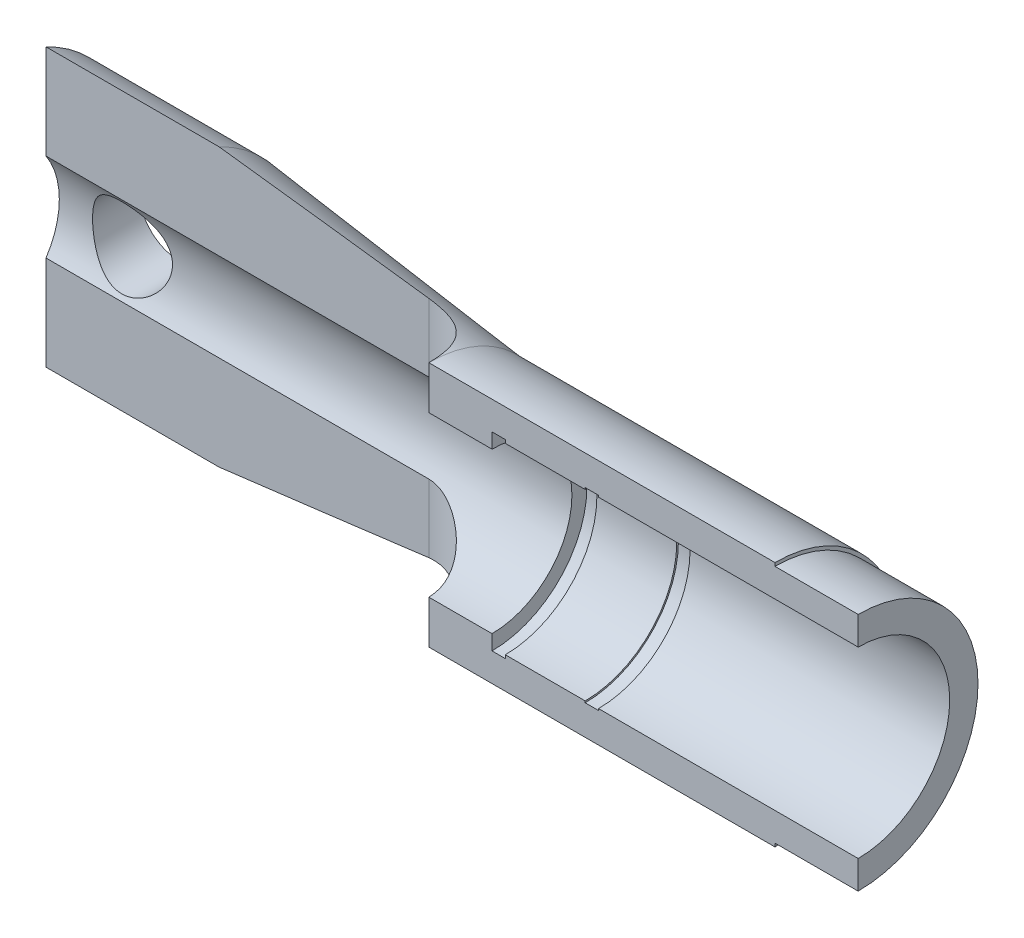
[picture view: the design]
ISO-10303-21;
HEADER;
FILE_DESCRIPTION(('STEP AP214'),'2;1');
FILE_NAME('part.step','',(''),(''),'','','');
FILE_SCHEMA(('AUTOMOTIVE_DESIGN { 1 0 10303 214 1 1 1 1 }'));
ENDSEC;
DATA;
#1=APPLICATION_CONTEXT('core data for automotive mechanical design processes');
#2=APPLICATION_PROTOCOL_DEFINITION('international standard','automotive_design',2000,#1);
#3=PRODUCT_CONTEXT('',#1,'mechanical');
#4=PRODUCT('Part','Part','',(#3));
#5=PRODUCT_RELATED_PRODUCT_CATEGORY('part','',(#4));
#6=PRODUCT_DEFINITION_FORMATION('','',#4);
#7=PRODUCT_DEFINITION_CONTEXT('part definition',#1,'design');
#8=PRODUCT_DEFINITION('design','',#6,#7);
#9=PRODUCT_DEFINITION_SHAPE('','',#8);
#10=(LENGTH_UNIT() NAMED_UNIT(*) SI_UNIT(.MILLI.,.METRE.));
#11=(NAMED_UNIT(*) PLANE_ANGLE_UNIT() SI_UNIT($,.RADIAN.));
#12=(NAMED_UNIT(*) SI_UNIT($,.STERADIAN.) SOLID_ANGLE_UNIT());
#13=UNCERTAINTY_MEASURE_WITH_UNIT(LENGTH_MEASURE(1.E-05),#10,'distance_accuracy_value','');
#14=(GEOMETRIC_REPRESENTATION_CONTEXT(3) GLOBAL_UNCERTAINTY_ASSIGNED_CONTEXT((#13)) GLOBAL_UNIT_ASSIGNED_CONTEXT((#10,
#11,#12)) REPRESENTATION_CONTEXT('',''));
#15=CARTESIAN_POINT('',(0.,0.,0.));
#16=DIRECTION('',(0.,0.,1.));
#17=DIRECTION('',(1.,0.,0.));
#18=AXIS2_PLACEMENT_3D('',#15,#16,#17);
#19=CARTESIAN_POINT('',(0.,0.,0.));
#20=DIRECTION('',(1.,0.,0.));
#21=DIRECTION('',(0.,0.,-1.));
#22=AXIS2_PLACEMENT_3D('',#19,#20,#21);
#23=CYLINDRICAL_SURFACE('',#22,27.5);
#24=CARTESIAN_POINT('',(-78.,0.,0.));
#25=DIRECTION('',(1.,0.,0.));
#26=DIRECTION('',(0.,0.,-1.));
#27=AXIS2_PLACEMENT_3D('',#24,#25,#26);
#28=CIRCLE('',#27,27.5);
#29=CARTESIAN_POINT('',(-78.,-27.5,1.92031473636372E-13));
#30=VERTEX_POINT('',#29);
#31=CARTESIAN_POINT('',(-78.,27.5,0.));
#32=VERTEX_POINT('',#31);
#33=EDGE_CURVE('E223',#30,#32,#28,.T.);
#34=ORIENTED_EDGE('',*,*,#33,.F.);
#35=DIRECTION('',(1.,0.,0.));
#36=VECTOR('',#35,1.);
#37=CARTESIAN_POINT('',(0.,-27.5,1.92031473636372E-13));
#38=LINE('',#37,#36);
#39=CARTESIAN_POINT('',(0.,-27.5,1.92031473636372E-13));
#40=VERTEX_POINT('',#39);
#41=EDGE_CURVE('E417',#30,#40,#38,.T.);
#42=ORIENTED_EDGE('',*,*,#41,.T.);
#43=CARTESIAN_POINT('',(0.,0.,0.));
#44=DIRECTION('',(1.,0.,0.));
#45=DIRECTION('',(0.,0.,-1.));
#46=AXIS2_PLACEMENT_3D('',#43,#44,#45);
#47=CIRCLE('',#46,27.5);
#48=CARTESIAN_POINT('',(0.,27.5,0.));
#49=VERTEX_POINT('',#48);
#50=EDGE_CURVE('E355',#40,#49,#47,.T.);
#51=ORIENTED_EDGE('',*,*,#50,.T.);
#52=DIRECTION('',(1.,0.,0.));
#53=VECTOR('',#52,1.);
#54=CARTESIAN_POINT('',(0.,27.5,0.));
#55=LINE('',#54,#53);
#56=EDGE_CURVE('E380',#32,#49,#55,.T.);
#57=ORIENTED_EDGE('',*,*,#56,.F.);
#58=EDGE_LOOP('',(#34,#42,#51,#57));
#59=FACE_BOUND('',#58,.T.);
#60=ADVANCED_FACE('F33',(#59),#23,.F.);
#61=CARTESIAN_POINT('',(-78.,-27.5,1.92031473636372E-13));
#62=DIRECTION('',(-1.,0.,0.));
#63=DIRECTION('',(0.,0.,1.));
#64=AXIS2_PLACEMENT_3D('',#61,#62,#63);
#65=PLANE('',#64);
#66=CARTESIAN_POINT('',(-78.,0.,0.));
#67=DIRECTION('',(1.,0.,0.));
#68=DIRECTION('',(0.,0.,-1.));
#69=AXIS2_PLACEMENT_3D('',#66,#67,#68);
#70=CIRCLE('',#69,28.);
#71=CARTESIAN_POINT('',(-78.,-28.,1.95522954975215E-13));
#72=VERTEX_POINT('',#71);
#73=CARTESIAN_POINT('',(-78.,28.,0.));
#74=VERTEX_POINT('',#73);
#75=EDGE_CURVE('E221',#72,#74,#70,.T.);
#76=ORIENTED_EDGE('',*,*,#75,.F.);
#77=DIRECTION('',(0.,1.,0.));
#78=VECTOR('',#77,1.);
#79=CARTESIAN_POINT('',(-78.,-27.5,1.92031473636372E-13));
#80=LINE('',#79,#78);
#81=EDGE_CURVE('E352',#72,#30,#80,.T.);
#82=ORIENTED_EDGE('',*,*,#81,.T.);
#83=ORIENTED_EDGE('',*,*,#33,.T.);
#84=DIRECTION('',(0.,-1.,0.));
#85=VECTOR('',#84,1.);
#86=CARTESIAN_POINT('',(-78.,27.5,0.));
#87=LINE('',#86,#85);
#88=EDGE_CURVE('E414',#74,#32,#87,.T.);
#89=ORIENTED_EDGE('',*,*,#88,.F.);
#90=EDGE_LOOP('',(#76,#82,#83,#89));
#91=FACE_BOUND('',#90,.T.);
#92=ADVANCED_FACE('F35',(#91),#65,.T.);
#93=CARTESIAN_POINT('',(0.,0.,0.));
#94=DIRECTION('',(1.,0.,0.));
#95=DIRECTION('',(0.,0.,-1.));
#96=AXIS2_PLACEMENT_3D('',#93,#94,#95);
#97=CYLINDRICAL_SURFACE('',#96,28.);
#98=CARTESIAN_POINT('',(-82.,0.,0.));
#99=DIRECTION('',(1.,0.,0.));
#100=DIRECTION('',(0.,0.,-1.));
#101=AXIS2_PLACEMENT_3D('',#98,#99,#100);
#102=CIRCLE('',#101,28.);
#103=CARTESIAN_POINT('',(-82.,-28.,1.95522954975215E-13));
#104=VERTEX_POINT('',#103);
#105=CARTESIAN_POINT('',(-82.,28.,0.));
#106=VERTEX_POINT('',#105);
#107=EDGE_CURVE('E219',#104,#106,#102,.T.);
#108=ORIENTED_EDGE('',*,*,#107,.F.);
#109=DIRECTION('',(1.,0.,0.));
#110=VECTOR('',#109,1.);
#111=CARTESIAN_POINT('',(-78.,-28.,1.95522954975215E-13));
#112=LINE('',#111,#110);
#113=EDGE_CURVE('E349',#104,#72,#112,.T.);
#114=ORIENTED_EDGE('',*,*,#113,.T.);
#115=ORIENTED_EDGE('',*,*,#75,.T.);
#116=DIRECTION('',(1.,0.,0.));
#117=VECTOR('',#116,1.);
#118=CARTESIAN_POINT('',(-78.,28.,0.));
#119=LINE('',#118,#117);
#120=EDGE_CURVE('E411',#106,#74,#119,.T.);
#121=ORIENTED_EDGE('',*,*,#120,.F.);
#122=EDGE_LOOP('',(#108,#114,#115,#121));
#123=FACE_BOUND('',#122,.T.);
#124=ADVANCED_FACE('F450',(#123),#97,.F.);
#125=CARTESIAN_POINT('',(-82.,-28.,1.95522954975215E-13));
#126=DIRECTION('',(1.,0.,0.));
#127=DIRECTION('',(0.,0.,-1.));
#128=AXIS2_PLACEMENT_3D('',#125,#126,#127);
#129=PLANE('',#128);
#130=CARTESIAN_POINT('',(-82.,0.,0.));
#131=DIRECTION('',(1.,0.,0.));
#132=DIRECTION('',(0.,0.,-1.));
#133=AXIS2_PLACEMENT_3D('',#130,#131,#132);
#134=CIRCLE('',#133,27.5);
#135=CARTESIAN_POINT('',(-82.,-27.5,1.92031473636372E-13));
#136=VERTEX_POINT('',#135);
#137=CARTESIAN_POINT('',(-82.,27.5,0.));
#138=VERTEX_POINT('',#137);
#139=EDGE_CURVE('E217',#136,#138,#134,.T.);
#140=ORIENTED_EDGE('',*,*,#139,.F.);
#141=DIRECTION('',(0.,-1.,0.));
#142=VECTOR('',#141,1.);
#143=CARTESIAN_POINT('',(-82.,-28.,1.95522954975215E-13));
#144=LINE('',#143,#142);
#145=EDGE_CURVE('E346',#136,#104,#144,.T.);
#146=ORIENTED_EDGE('',*,*,#145,.T.);
#147=ORIENTED_EDGE('',*,*,#107,.T.);
#148=DIRECTION('',(0.,1.,0.));
#149=VECTOR('',#148,1.);
#150=CARTESIAN_POINT('',(-82.,28.,0.));
#151=LINE('',#150,#149);
#152=EDGE_CURVE('E408',#138,#106,#151,.T.);
#153=ORIENTED_EDGE('',*,*,#152,.F.);
#154=EDGE_LOOP('',(#140,#146,#147,#153));
#155=FACE_BOUND('',#154,.T.);
#156=ADVANCED_FACE('F454',(#155),#129,.T.);
#157=CARTESIAN_POINT('',(0.,0.,0.));
#158=DIRECTION('',(1.,0.,0.));
#159=DIRECTION('',(0.,0.,-1.));
#160=AXIS2_PLACEMENT_3D('',#157,#158,#159);
#161=CYLINDRICAL_SURFACE('',#160,27.5);
#162=CARTESIAN_POINT('',(-106.,0.,0.));
#163=DIRECTION('',(1.,0.,0.));
#164=DIRECTION('',(0.,0.,-1.));
#165=AXIS2_PLACEMENT_3D('',#162,#163,#164);
#166=CIRCLE('',#165,27.5);
#167=CARTESIAN_POINT('',(-106.,-27.5,1.92031473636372E-13));
#168=VERTEX_POINT('',#167);
#169=CARTESIAN_POINT('',(-106.,27.5,0.));
#170=VERTEX_POINT('',#169);
#171=EDGE_CURVE('E215',#168,#170,#166,.T.);
#172=ORIENTED_EDGE('',*,*,#171,.F.);
#173=DIRECTION('',(1.,0.,0.));
#174=VECTOR('',#173,1.);
#175=CARTESIAN_POINT('',(-82.,-27.5,1.92031473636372E-13));
#176=LINE('',#175,#174);
#177=EDGE_CURVE('E343',#168,#136,#176,.T.);
#178=ORIENTED_EDGE('',*,*,#177,.T.);
#179=ORIENTED_EDGE('',*,*,#139,.T.);
#180=DIRECTION('',(1.,0.,0.));
#181=VECTOR('',#180,1.);
#182=CARTESIAN_POINT('',(-82.,27.5,0.));
#183=LINE('',#182,#181);
#184=EDGE_CURVE('E405',#170,#138,#183,.T.);
#185=ORIENTED_EDGE('',*,*,#184,.F.);
#186=EDGE_LOOP('',(#172,#178,#179,#185));
#187=FACE_BOUND('',#186,.T.);
#188=ADVANCED_FACE('F457',(#187),#161,.F.);
#189=CARTESIAN_POINT('',(-106.,-27.5,1.92031473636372E-13));
#190=DIRECTION('',(-1.,0.,0.));
#191=DIRECTION('',(0.,0.,1.));
#192=AXIS2_PLACEMENT_3D('',#189,#190,#191);
#193=PLANE('',#192);
#194=CARTESIAN_POINT('',(-106.,0.,0.));
#195=DIRECTION('',(1.,0.,0.));
#196=DIRECTION('',(0.,0.,-1.));
#197=AXIS2_PLACEMENT_3D('',#194,#195,#196);
#198=CIRCLE('',#197,28.5);
#199=CARTESIAN_POINT('',(-106.,-28.5,1.99014436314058E-13));
#200=VERTEX_POINT('',#199);
#201=CARTESIAN_POINT('',(-106.,28.5,0.));
#202=VERTEX_POINT('',#201);
#203=EDGE_CURVE('E213',#200,#202,#198,.T.);
#204=ORIENTED_EDGE('',*,*,#203,.F.);
#205=DIRECTION('',(0.,1.,0.));
#206=VECTOR('',#205,1.);
#207=CARTESIAN_POINT('',(-106.,-27.5,1.92031473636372E-13));
#208=LINE('',#207,#206);
#209=EDGE_CURVE('E340',#200,#168,#208,.T.);
#210=ORIENTED_EDGE('',*,*,#209,.T.);
#211=ORIENTED_EDGE('',*,*,#171,.T.);
#212=DIRECTION('',(0.,-1.,0.));
#213=VECTOR('',#212,1.);
#214=CARTESIAN_POINT('',(-106.,27.5,0.));
#215=LINE('',#214,#213);
#216=EDGE_CURVE('E402',#202,#170,#215,.T.);
#217=ORIENTED_EDGE('',*,*,#216,.F.);
#218=EDGE_LOOP('',(#204,#210,#211,#217));
#219=FACE_BOUND('',#218,.T.);
#220=ADVANCED_FACE('F460',(#219),#193,.T.);
#221=CARTESIAN_POINT('',(0.,0.,0.));
#222=DIRECTION('',(1.,0.,0.));
#223=DIRECTION('',(0.,0.,-1.));
#224=AXIS2_PLACEMENT_3D('',#221,#222,#223);
#225=CYLINDRICAL_SURFACE('',#224,28.5);
#226=CARTESIAN_POINT('',(-110.,0.,0.));
#227=DIRECTION('',(1.,0.,0.));
#228=DIRECTION('',(0.,0.,-1.));
#229=AXIS2_PLACEMENT_3D('',#226,#227,#228);
#230=CIRCLE('',#229,28.5);
#231=CARTESIAN_POINT('',(-110.,-28.5,1.99014436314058E-13));
#232=VERTEX_POINT('',#231);
#233=CARTESIAN_POINT('',(-110.,28.5,0.));
#234=VERTEX_POINT('',#233);
#235=EDGE_CURVE('E211',#232,#234,#230,.T.);
#236=ORIENTED_EDGE('',*,*,#235,.F.);
#237=DIRECTION('',(1.,0.,0.));
#238=VECTOR('',#237,1.);
#239=CARTESIAN_POINT('',(-106.,-28.5,1.99014436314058E-13));
#240=LINE('',#239,#238);
#241=EDGE_CURVE('E331',#232,#200,#240,.T.);
#242=ORIENTED_EDGE('',*,*,#241,.T.);
#243=ORIENTED_EDGE('',*,*,#203,.T.);
#244=DIRECTION('',(1.,0.,0.));
#245=VECTOR('',#244,1.);
#246=CARTESIAN_POINT('',(-106.,28.5,0.));
#247=LINE('',#246,#245);
#248=EDGE_CURVE('E399',#234,#202,#247,.T.);
#249=ORIENTED_EDGE('',*,*,#248,.F.);
#250=EDGE_LOOP('',(#236,#242,#243,#249));
#251=FACE_BOUND('',#250,.T.);
#252=ADVANCED_FACE('F464',(#251),#225,.F.);
#253=CARTESIAN_POINT('',(-110.,-28.5,1.99014436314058E-13));
#254=DIRECTION('',(1.,0.,0.));
#255=DIRECTION('',(0.,0.,-1.));
#256=AXIS2_PLACEMENT_3D('',#253,#254,#255);
#257=PLANE('',#256);
#258=CARTESIAN_POINT('',(-110.,0.,0.));
#259=DIRECTION('',(1.,0.,0.));
#260=DIRECTION('',(0.,0.,-1.));
#261=AXIS2_PLACEMENT_3D('',#258,#259,#260);
#262=CIRCLE('',#261,24.);
#263=CARTESIAN_POINT('',(-110.,-24.,1.6759110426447E-13));
#264=VERTEX_POINT('',#263);
#265=CARTESIAN_POINT('',(-110.,24.,0.));
#266=VERTEX_POINT('',#265);
#267=EDGE_CURVE('E203',#264,#266,#262,.T.);
#268=ORIENTED_EDGE('',*,*,#267,.F.);
#269=DIRECTION('',(0.,-1.,0.));
#270=VECTOR('',#269,1.);
#271=CARTESIAN_POINT('',(-110.,-28.5,1.99014436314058E-13));
#272=LINE('',#271,#270);
#273=EDGE_CURVE('E328',#264,#232,#272,.T.);
#274=ORIENTED_EDGE('',*,*,#273,.T.);
#275=ORIENTED_EDGE('',*,*,#235,.T.);
#276=DIRECTION('',(0.,1.,0.));
#277=VECTOR('',#276,1.);
#278=CARTESIAN_POINT('',(-110.,28.5,0.));
#279=LINE('',#278,#277);
#280=EDGE_CURVE('E396',#266,#234,#279,.T.);
#281=ORIENTED_EDGE('',*,*,#280,.F.);
#282=EDGE_LOOP('',(#268,#274,#275,#281));
#283=FACE_BOUND('',#282,.T.);
#284=ADVANCED_FACE('F289',(#283),#257,.T.);
#285=CARTESIAN_POINT('',(0.,0.,0.));
#286=DIRECTION('',(1.,0.,0.));
#287=DIRECTION('',(0.,0.,-1.));
#288=AXIS2_PLACEMENT_3D('',#285,#286,#287);
#289=CYLINDRICAL_SURFACE('',#288,24.);
#290=CARTESIAN_POINT('',(-230.,0.,-24.));
#291=CARTESIAN_POINT('',(-230.000001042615,0.315573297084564,-23.9999990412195));
#292=CARTESIAN_POINT('',(-230.012462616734,0.631168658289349,-23.99376130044));
#293=CARTESIAN_POINT('',(-230.062166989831,1.26003507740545,-23.9689674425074));
#294=CARTESIAN_POINT('',(-230.09942056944,1.57330506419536,-23.950405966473));
#295=CARTESIAN_POINT('',(-230.198350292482,2.19555871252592,-23.9014034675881));
#296=CARTESIAN_POINT('',(-230.260067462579,2.50453426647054,-23.8709424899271));
#297=CARTESIAN_POINT('',(-230.407205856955,3.11541819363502,-23.7989236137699));
#298=CARTESIAN_POINT('',(-230.492624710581,3.41732727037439,-23.7573668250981));
#299=CARTESIAN_POINT('',(-230.685882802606,4.01096204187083,-23.6643636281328));
#300=CARTESIAN_POINT('',(-230.793633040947,4.30272294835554,-23.6129565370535));
#301=CARTESIAN_POINT('',(-231.030733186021,4.87558118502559,-23.5013590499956));
#302=CARTESIAN_POINT('',(-231.160083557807,5.15667828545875,-23.4411684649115));
#303=CARTESIAN_POINT('',(-231.439243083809,5.70661678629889,-23.3133908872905));
#304=CARTESIAN_POINT('',(-231.589044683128,5.97546266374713,-23.2458066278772));
#305=CARTESIAN_POINT('',(-231.908104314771,6.49983696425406,-23.1046723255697));
#306=CARTESIAN_POINT('',(-232.07737001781,6.75536007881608,-23.0311199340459));
#307=CARTESIAN_POINT('',(-232.445005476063,7.26685384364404,-22.8750644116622));
#308=CARTESIAN_POINT('',(-232.644514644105,7.52192271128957,-22.7922889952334));
#309=CARTESIAN_POINT('',(-233.062934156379,8.01456886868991,-22.6237591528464));
#310=CARTESIAN_POINT('',(-233.281845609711,8.25214515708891,-22.5380045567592));
#311=CARTESIAN_POINT('',(-233.738046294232,8.70886687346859,-22.3654927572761));
#312=CARTESIAN_POINT('',(-233.975346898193,8.92800071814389,-22.2787349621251));
#313=CARTESIAN_POINT('',(-234.467122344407,9.34666033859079,-22.1063612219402));
#314=CARTESIAN_POINT('',(-234.721600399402,9.54618242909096,-22.0207454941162));
#315=CARTESIAN_POINT('',(-235.267031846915,9.93925333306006,-21.846304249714));
#316=CARTESIAN_POINT('',(-235.559282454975,10.13112679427,-21.7577480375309));
#317=CARTESIAN_POINT('',(-236.160750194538,10.4893097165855,-21.5873508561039));
#318=CARTESIAN_POINT('',(-236.46996006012,10.6556300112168,-21.5055070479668));
#319=CARTESIAN_POINT('',(-237.103639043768,10.9612653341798,-21.3513457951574));
#320=CARTESIAN_POINT('',(-237.428103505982,11.1005885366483,-21.2790254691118));
#321=CARTESIAN_POINT('',(-238.090263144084,11.3507342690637,-21.1466519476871));
#322=CARTESIAN_POINT('',(-238.427956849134,11.4615599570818,-21.0865973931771));
#323=CARTESIAN_POINT('',(-239.093498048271,11.6475055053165,-20.9844274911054));
#324=CARTESIAN_POINT('',(-239.420727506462,11.7243636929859,-20.9414544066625));
#325=CARTESIAN_POINT('',(-240.082059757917,11.8505186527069,-20.8703253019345));
#326=CARTESIAN_POINT('',(-240.416162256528,11.8998166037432,-20.8421686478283));
#327=CARTESIAN_POINT('',(-241.088017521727,11.9700573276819,-20.8019079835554));
#328=CARTESIAN_POINT('',(-241.425766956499,11.9910240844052,-20.7897903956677));
#329=CARTESIAN_POINT('',(-242.102003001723,12.0043296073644,-20.7821111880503));
#330=CARTESIAN_POINT('',(-242.440489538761,11.9966711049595,-20.7865479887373));
#331=CARTESIAN_POINT('',(-243.074548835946,11.9554954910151,-20.8102516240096));
#332=CARTESIAN_POINT('',(-243.370405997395,11.9251852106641,-20.8276786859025));
#333=CARTESIAN_POINT('',(-243.958091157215,11.8428838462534,-20.8745861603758));
#334=CARTESIAN_POINT('',(-244.249919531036,11.7908947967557,-20.9040654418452));
#335=CARTESIAN_POINT('',(-244.827720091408,11.6658222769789,-20.974120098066));
#336=CARTESIAN_POINT('',(-245.113690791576,11.5927335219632,-21.0146982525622));
#337=CARTESIAN_POINT('',(-245.678040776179,11.4262234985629,-21.1056960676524));
#338=CARTESIAN_POINT('',(-245.956419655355,11.3328011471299,-21.1561162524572));
#339=CARTESIAN_POINT('',(-246.510449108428,11.1240948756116,-21.2666114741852));
#340=CARTESIAN_POINT('',(-246.785889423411,11.008357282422,-21.3268820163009));
#341=CARTESIAN_POINT('',(-247.326119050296,10.7573792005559,-21.4545709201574));
#342=CARTESIAN_POINT('',(-247.590904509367,10.6221317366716,-21.5219918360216));
#343=CARTESIAN_POINT('',(-248.108671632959,10.3330565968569,-21.6622655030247));
#344=CARTESIAN_POINT('',(-248.361651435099,10.1792260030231,-21.7351191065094));
#345=CARTESIAN_POINT('',(-248.854818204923,9.85386986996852,-21.884544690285));
#346=CARTESIAN_POINT('',(-249.095004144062,9.68234291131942,-21.9611169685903));
#347=CARTESIAN_POINT('',(-249.591370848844,9.29953768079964,-22.1261694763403));
#348=CARTESIAN_POINT('',(-249.845704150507,9.08597796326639,-22.214926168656));
#349=CARTESIAN_POINT('',(-250.335672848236,8.63866698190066,-22.392662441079));
#350=CARTESIAN_POINT('',(-250.571314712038,8.40492276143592,-22.4816419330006));
#351=CARTESIAN_POINT('',(-251.022976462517,7.91809528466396,-22.6576877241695));
#352=CARTESIAN_POINT('',(-251.238978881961,7.66499517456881,-22.7447522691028));
#353=CARTESIAN_POINT('',(-251.649744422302,7.14095403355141,-22.9146812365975));
#354=CARTESIAN_POINT('',(-251.844516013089,6.87002018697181,-22.9975473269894));
#355=CARTESIAN_POINT('',(-252.220155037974,6.29847321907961,-23.1607776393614));
#356=CARTESIAN_POINT('',(-252.399945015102,5.99706449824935,-23.2408432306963));
#357=CARTESIAN_POINT('',(-252.73324308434,5.3778359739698,-23.3918881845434));
#358=CARTESIAN_POINT('',(-252.886749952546,5.06001540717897,-23.4628671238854));
#359=CARTESIAN_POINT('',(-253.165753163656,4.41031227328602,-23.5936190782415));
#360=CARTESIAN_POINT('',(-253.291267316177,4.07843880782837,-23.6533992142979));
#361=CARTESIAN_POINT('',(-253.512860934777,3.40298717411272,-23.7599772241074));
#362=CARTESIAN_POINT('',(-253.608943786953,3.05941035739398,-23.8067765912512));
#363=CARTESIAN_POINT('',(-253.763679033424,2.39232098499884,-23.8826295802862));
#364=CARTESIAN_POINT('',(-253.824772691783,2.0695039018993,-23.9128320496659));
#365=CARTESIAN_POINT('',(-253.920338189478,1.41900713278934,-23.9602323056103));
#366=CARTESIAN_POINT('',(-253.954811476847,1.09132771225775,-23.9774307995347));
#367=CARTESIAN_POINT('',(-253.996671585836,0.433945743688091,-23.9983291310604));
#368=CARTESIAN_POINT('',(-254.004069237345,0.104244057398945,-24.0020343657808));
#369=CARTESIAN_POINT('',(-253.991706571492,-0.55451434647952,-23.9958536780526));
#370=CARTESIAN_POINT('',(-253.971947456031,-0.883571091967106,-23.9859683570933));
#371=CARTESIAN_POINT('',(-253.908125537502,-1.51283492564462,-23.9541805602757));
#372=CARTESIAN_POINT('',(-253.866068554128,-1.81329854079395,-23.9332705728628));
#373=CARTESIAN_POINT('',(-253.759555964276,-2.40924407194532,-23.8806409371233));
#374=CARTESIAN_POINT('',(-253.695101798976,-2.70472630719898,-23.8489219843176));
#375=CARTESIAN_POINT('',(-253.544463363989,-3.28882114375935,-23.7754141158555));
#376=CARTESIAN_POINT('',(-253.458277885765,-3.57743336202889,-23.7336246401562));
#377=CARTESIAN_POINT('',(-253.26500583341,-4.14606176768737,-23.6409215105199));
#378=CARTESIAN_POINT('',(-253.157918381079,-4.42607759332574,-23.5900074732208));
#379=CARTESIAN_POINT('',(-252.920452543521,-4.98379006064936,-23.4786068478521));
#380=CARTESIAN_POINT('',(-252.789499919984,-5.26119588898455,-23.4178897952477));
#381=CARTESIAN_POINT('',(-252.507494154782,-5.80397665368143,-23.2893040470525));
#382=CARTESIAN_POINT('',(-252.356433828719,-6.06934724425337,-23.2214327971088));
#383=CARTESIAN_POINT('',(-252.035288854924,-6.58678352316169,-23.0799964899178));
#384=CARTESIAN_POINT('',(-251.865200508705,-6.83884661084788,-23.0064303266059));
#385=CARTESIAN_POINT('',(-251.507079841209,-7.32853684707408,-22.8551575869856));
#386=CARTESIAN_POINT('',(-251.319048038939,-7.56616441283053,-22.7774511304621));
#387=CARTESIAN_POINT('',(-250.906697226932,-8.04867125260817,-22.6117268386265));
#388=CARTESIAN_POINT('',(-250.680628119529,-8.29196695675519,-22.5234462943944));
#389=CARTESIAN_POINT('',(-250.209292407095,-8.75885661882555,-22.346024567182));
#390=CARTESIAN_POINT('',(-249.964024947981,-8.98244969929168,-22.2568833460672));
#391=CARTESIAN_POINT('',(-249.455351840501,-9.40892924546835,-22.0799769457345));
#392=CARTESIAN_POINT('',(-249.191935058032,-9.61180280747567,-21.992212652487));
#393=CARTESIAN_POINT('',(-248.648295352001,-9.99554332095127,-21.8204793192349));
#394=CARTESIAN_POINT('',(-248.36807001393,-10.1764070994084,-21.7365108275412));
#395=CARTESIAN_POINT('',(-247.778093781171,-10.5231332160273,-21.5708686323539));
#396=CARTESIAN_POINT('',(-247.467569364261,-10.6878325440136,-21.4895069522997));
#397=CARTESIAN_POINT('',(-246.831424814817,-10.9900529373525,-21.3365281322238));
#398=CARTESIAN_POINT('',(-246.505812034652,-11.1275870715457,-21.2649063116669));
#399=CARTESIAN_POINT('',(-245.841740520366,-11.3739321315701,-21.1341695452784));
#400=CARTESIAN_POINT('',(-245.503292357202,-11.4827661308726,-21.075044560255));
#401=CARTESIAN_POINT('',(-244.815940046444,-11.6703611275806,-20.9717472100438));
#402=CARTESIAN_POINT('',(-244.467037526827,-11.7491267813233,-20.9275725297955));
#403=CARTESIAN_POINT('',(-243.795770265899,-11.8692907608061,-20.8596313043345));
#404=CARTESIAN_POINT('',(-243.474073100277,-11.9135502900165,-20.8343127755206));
#405=CARTESIAN_POINT('',(-242.827327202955,-11.9758523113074,-20.7985641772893));
#406=CARTESIAN_POINT('',(-242.502278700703,-11.9938965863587,-20.7881330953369));
#407=CARTESIAN_POINT('',(-241.851783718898,-12.0034916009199,-20.7825941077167));
#408=CARTESIAN_POINT('',(-241.526337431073,-11.9950521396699,-20.7874805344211));
#409=CARTESIAN_POINT('',(-240.877793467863,-11.9518307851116,-20.8123607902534));
#410=CARTESIAN_POINT('',(-240.554695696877,-11.9170499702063,-20.8323540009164));
#411=CARTESIAN_POINT('',(-239.944262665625,-11.8262366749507,-20.8840261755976));
#412=CARTESIAN_POINT('',(-239.656462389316,-11.7725547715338,-20.9144046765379));
#413=CARTESIAN_POINT('',(-239.086724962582,-11.6446594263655,-20.9858826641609));
#414=CARTESIAN_POINT('',(-238.804789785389,-11.5704391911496,-21.0269856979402));
#415=CARTESIAN_POINT('',(-238.248531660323,-11.4022327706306,-21.1186705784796));
#416=CARTESIAN_POINT('',(-237.974207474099,-11.3082498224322,-21.16925087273));
#417=CARTESIAN_POINT('',(-237.434361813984,-11.1012865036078,-21.278513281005));
#418=CARTESIAN_POINT('',(-237.168844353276,-10.9882976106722,-21.3371990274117));
#419=CARTESIAN_POINT('',(-236.630448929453,-10.7360194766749,-21.4653024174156));
#420=CARTESIAN_POINT('',(-236.35826698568,-10.5954764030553,-21.535175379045));
#421=CARTESIAN_POINT('',(-235.826545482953,-10.2947448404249,-21.6805469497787));
#422=CARTESIAN_POINT('',(-235.56700705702,-10.1345545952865,-21.7560460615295));
#423=CARTESIAN_POINT('',(-235.061538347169,-9.79542789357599,-21.9108269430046));
#424=CARTESIAN_POINT('',(-234.815612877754,-9.61648486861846,-21.9901100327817));
#425=CARTESIAN_POINT('',(-234.338397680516,-9.24078422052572,-22.1506126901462));
#426=CARTESIAN_POINT('',(-234.107110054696,-9.04402404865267,-22.2318325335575));
#427=CARTESIAN_POINT('',(-233.632893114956,-8.60856403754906,-22.4043282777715));
#428=CARTESIAN_POINT('',(-233.391976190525,-8.36767481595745,-22.4956242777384));
#429=CARTESIAN_POINT('',(-232.931178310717,-7.86590560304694,-22.6759471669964));
#430=CARTESIAN_POINT('',(-232.711291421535,-7.60503128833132,-22.7649746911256));
#431=CARTESIAN_POINT('',(-232.293706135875,-7.06432051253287,-22.9385275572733));
#432=CARTESIAN_POINT('',(-232.096025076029,-6.78446950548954,-23.023049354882));
#433=CARTESIAN_POINT('',(-231.724545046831,-6.20747453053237,-23.1852766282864));
#434=CARTESIAN_POINT('',(-231.550744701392,-5.91033156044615,-23.2629824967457));
#435=CARTESIAN_POINT('',(-231.227374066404,-5.29822602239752,-23.4100101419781));
#436=CARTESIAN_POINT('',(-231.077989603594,-4.98314936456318,-23.4792666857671));
#437=CARTESIAN_POINT('',(-230.806583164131,-4.33929014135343,-23.6067410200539));
#438=CARTESIAN_POINT('',(-230.684557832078,-4.01050926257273,-23.664960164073));
#439=CARTESIAN_POINT('',(-230.469575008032,-3.34247342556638,-23.7685053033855));
#440=CARTESIAN_POINT('',(-230.376548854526,-3.00324533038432,-23.8138617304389));
#441=CARTESIAN_POINT('',(-230.220468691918,-2.31656786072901,-23.8904314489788));
#442=CARTESIAN_POINT('',(-230.157396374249,-1.96912364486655,-23.9216533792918));
#443=CARTESIAN_POINT('',(-230.07326131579,-1.35130022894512,-23.9634331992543));
#444=CARTESIAN_POINT('',(-230.045811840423,-1.08198201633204,-23.9771217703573));
#445=CARTESIAN_POINT('',(-230.009180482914,-0.541781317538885,-23.9954057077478));
#446=CARTESIAN_POINT('',(-229.999999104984,-0.27089878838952,-24.0000008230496));
#447=CARTESIAN_POINT('',(-230.,0.,-24.));
#448=B_SPLINE_CURVE_WITH_KNOTS('',3,(#290,#291,#292,#293,#294,#295,#296,#297,#298,#299,#300,
#301,#302,#303,#304,#305,#306,#307,#308,#309,#310,#311,#312,#313,#314,#315,#316,#317,#318,#319,
#320,#321,#322,#323,#324,#325,#326,#327,#328,#329,#330,#331,#332,#333,#334,#335,#336,#337,#338,
#339,#340,#341,#342,#343,#344,#345,#346,#347,#348,#349,#350,#351,#352,#353,#354,#355,#356,#357,
#358,#359,#360,#361,#362,#363,#364,#365,#366,#367,#368,#369,#370,#371,#372,#373,#374,#375,#376,
#377,#378,#379,#380,#381,#382,#383,#384,#385,#386,#387,#388,#389,#390,#391,#392,#393,#394,#395,
#396,#397,#398,#399,#400,#401,#402,#403,#404,#405,#406,#407,#408,#409,#410,#411,#412,#413,#414,
#415,#416,#417,#418,#419,#420,#421,#422,#423,#424,#425,#426,#427,#428,#429,#430,#431,#432,#433,
#434,#435,#436,#437,#438,#439,#440,#441,#442,#443,#444,#445,#446,#447),.UNSPECIFIED.,.T.,.F.,(4,
2,2,2,2,2,2,2,2,2,2,2,2,2,2,2,2,2,2,2,2,2,2,2,2,2,2,2,2,2,2,2,2,2,2,2,2,2,2,2,2,2,2,2,2,2,2,2,2,
2,2,2,2,2,2,2,2,2,2,2,2,2,2,2,2,2,2,2,2,2,2,2,2,2,2,2,2,2,4),(0.,0.946452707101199,
1.89331724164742,2.84177647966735,3.79014088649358,4.7347959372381,5.67947132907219,
6.62379868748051,7.56849948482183,8.57015528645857,9.57186838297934,10.5742060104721,
11.5767316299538,12.6573337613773,13.7374764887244,14.8172916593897,15.8969871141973,
16.9121438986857,17.9272572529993,18.9415107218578,19.9556674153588,20.8483627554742,
21.7409743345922,22.6338096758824,23.5266925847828,24.440125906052,25.3538866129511,
26.2677909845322,27.1817687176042,28.2119200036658,29.2417132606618,30.2724136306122,
31.3027012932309,32.381211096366,33.4597711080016,34.5376429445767,35.6153907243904,
36.603863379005,37.5922822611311,38.5803057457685,39.5682855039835,40.4795666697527,
41.3907892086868,42.3020624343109,43.2133739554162,44.1505216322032,45.0880050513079,
46.0256710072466,46.9633098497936,47.9931243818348,49.0229847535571,50.0534826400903,
51.0841289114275,52.1650777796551,53.24550534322,54.3250616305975,55.4044506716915,
56.3802259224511,57.3559348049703,58.3312827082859,59.3065906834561,60.1886227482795,
61.0709469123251,61.953126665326,62.8357030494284,63.7773264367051,64.7190340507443,
65.6610726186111,66.603246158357,67.6601582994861,68.7167713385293,69.7742036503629,
70.831575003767,71.8966527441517,72.961599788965,74.0240058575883,75.0857617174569,
75.8982062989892,76.7106733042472),.UNSPECIFIED.);
#449=CARTESIAN_POINT('',(-230.,0.,-24.));
#450=VERTEX_POINT('',#449);
#451=EDGE_CURVE('E184',#450,#450,#448,.T.);
#452=ORIENTED_EDGE('',*,*,#451,.F.);
#453=EDGE_LOOP('',(#452));
#454=FACE_BOUND('',#453,.T.);
#455=DIRECTION('',(1.,0.,0.));
#456=VECTOR('',#455,1.);
#457=CARTESIAN_POINT('',(0.,-13.2664991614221,-19.9999999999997));
#458=LINE('',#457,#456);
#459=CARTESIAN_POINT('',(-149.,-13.2664991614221,-19.9999999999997));
#460=VERTEX_POINT('',#459);
#461=CARTESIAN_POINT('',(-264.,-13.2664991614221,-19.9999999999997));
#462=VERTEX_POINT('',#461);
#463=EDGE_CURVE('E322',#460,#462,#458,.F.);
#464=ORIENTED_EDGE('',*,*,#463,.F.);
#465=CARTESIAN_POINT('',(-129.,-24.,1.74938985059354E-13));
#466=CARTESIAN_POINT('',(-128.999993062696,-24.0000072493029,-0.238682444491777));
#467=CARTESIAN_POINT('',(-129.004272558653,-23.9964395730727,-0.477360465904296));
#468=CARTESIAN_POINT('',(-129.021352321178,-23.9822084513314,-0.954188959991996));
#469=CARTESIAN_POINT('',(-129.034152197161,-23.9715453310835,-1.19233945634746));
#470=CARTESIAN_POINT('',(-129.06820886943,-23.943187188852,-1.6674520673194));
#471=CARTESIAN_POINT('',(-129.089459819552,-23.9254970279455,-1.90441488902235));
#472=CARTESIAN_POINT('',(-129.140310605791,-23.8831963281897,-2.37680451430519));
#473=CARTESIAN_POINT('',(-129.169910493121,-23.8585857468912,-2.61223130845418));
#474=CARTESIAN_POINT('',(-129.270528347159,-23.7750001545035,-3.31189563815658));
#475=CARTESIAN_POINT('',(-129.353639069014,-23.7060418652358,-3.77329657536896));
#476=CARTESIAN_POINT('',(-129.550833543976,-23.5428762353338,-4.68482014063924));
#477=CARTESIAN_POINT('',(-129.664921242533,-23.4486656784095,-5.13494132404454));
#478=CARTESIAN_POINT('',(-129.921949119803,-23.2371836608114,-6.01994428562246));
#479=CARTESIAN_POINT('',(-130.064813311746,-23.1199729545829,-6.45486273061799));
#480=CARTESIAN_POINT('',(-130.377598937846,-22.8645070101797,-7.30840731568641));
#481=CARTESIAN_POINT('',(-130.547519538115,-22.7262524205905,-7.7270339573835));
#482=CARTESIAN_POINT('',(-130.912706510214,-22.4307523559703,-8.5470227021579));
#483=CARTESIAN_POINT('',(-131.108014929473,-22.273475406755,-8.94835465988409));
#484=CARTESIAN_POINT('',(-131.521806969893,-21.942466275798,-9.73186217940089));
#485=CARTESIAN_POINT('',(-131.740295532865,-21.7687305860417,-10.1140336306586));
#486=CARTESIAN_POINT('',(-132.28261708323,-21.3408942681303,-10.9948073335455));
#487=CARTESIAN_POINT('',(-132.615716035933,-21.0806720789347,-11.4847626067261));
#488=CARTESIAN_POINT('',(-133.31774732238,-20.5397889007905,-12.4262647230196));
#489=CARTESIAN_POINT('',(-133.686691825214,-20.2591209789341,-12.8777984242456));
#490=CARTESIAN_POINT('',(-134.458073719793,-19.6825242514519,-13.742963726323));
#491=CARTESIAN_POINT('',(-134.860586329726,-19.3865617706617,-14.156505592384));
#492=CARTESIAN_POINT('',(-135.696065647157,-18.7859067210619,-14.9443990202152));
#493=CARTESIAN_POINT('',(-136.129028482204,-18.481215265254,-15.3187555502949));
#494=CARTESIAN_POINT('',(-137.032437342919,-17.8636982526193,-16.0348300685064));
#495=CARTESIAN_POINT('',(-137.503424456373,-17.5508258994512,-16.3758251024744));
#496=CARTESIAN_POINT('',(-138.475690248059,-16.9298844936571,-17.0169976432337));
#497=CARTESIAN_POINT('',(-138.976979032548,-16.6218170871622,-17.3171614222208));
#498=CARTESIAN_POINT('',(-140.009630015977,-16.0203188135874,-17.8750389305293));
#499=CARTESIAN_POINT('',(-140.540930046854,-15.7268598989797,-18.1328363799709));
#500=CARTESIAN_POINT('',(-141.361871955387,-15.3064087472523,-18.4864142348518));
#501=CARTESIAN_POINT('',(-141.639425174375,-15.1695885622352,-18.5987231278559));
#502=CARTESIAN_POINT('',(-142.202800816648,-14.9043630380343,-18.8119362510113));
#503=CARTESIAN_POINT('',(-142.488624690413,-14.7759591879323,-18.9128384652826));
#504=CARTESIAN_POINT('',(-143.436219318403,-14.3736355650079,-19.2229622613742));
#505=CARTESIAN_POINT('',(-144.116129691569,-14.1211393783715,-19.4077201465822));
#506=CARTESIAN_POINT('',(-145.164413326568,-13.8058453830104,-19.6320005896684));
#507=CARTESIAN_POINT('',(-145.517907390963,-13.711437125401,-19.6978790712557));
#508=CARTESIAN_POINT('',(-146.233465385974,-13.5474209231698,-19.8110396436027));
#509=CARTESIAN_POINT('',(-146.595524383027,-13.477799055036,-19.8583321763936));
#510=CARTESIAN_POINT('',(-147.296354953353,-13.3713308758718,-19.9301616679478));
#511=CARTESIAN_POINT('',(-147.634628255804,-13.3322810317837,-19.95623540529));
#512=CARTESIAN_POINT('',(-148.144720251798,-13.2929510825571,-19.9824340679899));
#513=CARTESIAN_POINT('',(-148.315521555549,-13.2830481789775,-19.989015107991));
#514=CARTESIAN_POINT('',(-148.657540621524,-13.269816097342,-19.9978002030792));
#515=CARTESIAN_POINT('',(-148.828758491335,-13.2664888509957,-20.0000029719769));
#516=CARTESIAN_POINT('',(-149.,-13.2664991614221,-19.9999999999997));
#517=B_SPLINE_CURVE_WITH_KNOTS('',3,(#465,#466,#467,#468,#469,#470,#471,#472,#473,#474,#475,
#476,#477,#478,#479,#480,#481,#482,#483,#484,#485,#486,#487,#488,#489,#490,#491,#492,#493,#494,
#495,#496,#497,#498,#499,#500,#501,#502,#503,#504,#505,#506,#507,#508,#509,#510,#511,#512,#513,
#514,#515,#516),.UNSPECIFIED.,.F.,.F.,(4,2,2,2,2,2,2,2,2,2,2,2,2,2,2,2,2,2,2,2,2,2,2,2,2,4),(0.,
0.71597444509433,1.43191607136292,2.14736329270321,2.86281490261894,4.28237144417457,
5.7021088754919,7.11814539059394,8.53413827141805,9.95250694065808,11.371178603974,
13.3096611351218,15.2488040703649,17.1924153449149,19.1357798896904,21.1147206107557,
23.0943250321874,25.0699692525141,26.0571592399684,27.0445234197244,29.2810473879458,
30.395254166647,31.5088340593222,32.5319287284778,33.0454103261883,33.5590427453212),.UNSPECIFIED.);
#518=CARTESIAN_POINT('',(-129.,-24.,0.));
#519=VERTEX_POINT('',#518);
#520=EDGE_CURVE('E279',#519,#460,#517,.T.);
#521=ORIENTED_EDGE('',*,*,#520,.F.);
#522=DIRECTION('',(1.,0.,0.));
#523=VECTOR('',#522,1.);
#524=CARTESIAN_POINT('',(-110.,-24.,1.6759110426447E-13));
#525=LINE('',#524,#523);
#526=EDGE_CURVE('E319',#519,#264,#525,.T.);
#527=ORIENTED_EDGE('',*,*,#526,.T.);
#528=ORIENTED_EDGE('',*,*,#267,.T.);
#529=DIRECTION('',(1.,0.,0.));
#530=VECTOR('',#529,1.);
#531=CARTESIAN_POINT('',(-110.,24.,0.));
#532=LINE('',#531,#530);
#533=CARTESIAN_POINT('',(-129.,24.,0.));
#534=VERTEX_POINT('',#533);
#535=EDGE_CURVE('E394',#534,#266,#532,.T.);
#536=ORIENTED_EDGE('',*,*,#535,.F.);
#537=CARTESIAN_POINT('',(-149.,13.2664991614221,-19.9999999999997));
#538=CARTESIAN_POINT('',(-148.821346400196,13.2664874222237,-20.0000032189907));
#539=CARTESIAN_POINT('',(-148.642721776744,13.2701097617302,-19.9976054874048));
#540=CARTESIAN_POINT('',(-148.285913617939,13.2845098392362,-19.9880441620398));
#541=CARTESIAN_POINT('',(-148.107730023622,13.2952865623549,-19.9808812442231));
#542=CARTESIAN_POINT('',(-147.575101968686,13.3381194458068,-19.9523385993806));
#543=CARTESIAN_POINT('',(-147.221810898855,13.3806792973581,-19.9239046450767));
#544=CARTESIAN_POINT('',(-146.526514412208,13.4908059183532,-19.8494945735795));
#545=CARTESIAN_POINT('',(-146.184419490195,13.5579973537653,-19.8037814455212));
#546=CARTESIAN_POINT('',(-145.507866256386,13.7144660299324,-19.6957469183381));
#547=CARTESIAN_POINT('',(-145.173412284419,13.8037554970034,-19.6334163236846));
#548=CARTESIAN_POINT('',(-144.382476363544,14.0402269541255,-19.4653676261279));
#549=CARTESIAN_POINT('',(-143.930231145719,14.1963222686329,-19.3522472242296));
#550=CARTESIAN_POINT('',(-143.044404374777,14.5362143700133,-19.0982578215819));
#551=CARTESIAN_POINT('',(-142.610830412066,14.7200222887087,-18.957377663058));
#552=CARTESIAN_POINT('',(-141.758928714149,15.109216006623,-18.6486929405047));
#553=CARTESIAN_POINT('',(-141.340748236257,15.3147605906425,-18.4806847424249));
#554=CARTESIAN_POINT('',(-140.522683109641,15.73985014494,-18.1200140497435));
#555=CARTESIAN_POINT('',(-140.122798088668,15.959394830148,-17.9273520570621));
#556=CARTESIAN_POINT('',(-139.167390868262,16.5065341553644,-17.4277223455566));
#557=CARTESIAN_POINT('',(-138.621310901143,16.8389475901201,-17.1079020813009));
#558=CARTESIAN_POINT('',(-137.564313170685,17.510244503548,-16.4201906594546));
#559=CARTESIAN_POINT('',(-137.053410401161,17.8491306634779,-16.0522791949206));
#560=CARTESIAN_POINT('',(-136.068244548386,18.5230022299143,-15.26972504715));
#561=CARTESIAN_POINT('',(-135.593904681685,18.857994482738,-14.8551850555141));
#562=CARTESIAN_POINT('',(-134.682514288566,19.5164363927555,-13.9788756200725));
#563=CARTESIAN_POINT('',(-134.245449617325,19.8398904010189,-13.5171242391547));
#564=CARTESIAN_POINT('',(-133.500018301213,20.4010495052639,-12.6492988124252));
#565=CARTESIAN_POINT('',(-133.183998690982,20.6424073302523,-12.2521433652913));
#566=CARTESIAN_POINT('',(-132.579193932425,21.1093800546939,-11.4288247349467));
#567=CARTESIAN_POINT('',(-132.290407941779,21.3349954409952,-11.0026624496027));
#568=CARTESIAN_POINT('',(-131.742938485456,21.7664378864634,-10.1223569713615));
#569=CARTESIAN_POINT('',(-131.48422842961,21.9722823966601,-9.66823904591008));
#570=CARTESIAN_POINT('',(-131.120946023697,22.2633183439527,-8.96709202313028));
#571=CARTESIAN_POINT('',(-131.00398713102,22.3573712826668,-8.73005932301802));
#572=CARTESIAN_POINT('',(-130.778672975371,22.5391286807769,-8.24946631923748));
#573=CARTESIAN_POINT('',(-130.67031997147,22.6268314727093,-8.00590432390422));
#574=CARTESIAN_POINT('',(-130.394683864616,22.8505513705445,-7.35107120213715));
#575=CARTESIAN_POINT('',(-130.235258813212,22.9806108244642,-6.93439212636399));
#576=CARTESIAN_POINT('',(-129.943187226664,23.2197132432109,-6.08597868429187));
#577=CARTESIAN_POINT('',(-129.810535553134,23.3287602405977,-5.65424722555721));
#578=CARTESIAN_POINT('',(-129.573976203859,23.523730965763,-4.77858884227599));
#579=CARTESIAN_POINT('',(-129.470023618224,23.6096908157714,-4.33468218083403));
#580=CARTESIAN_POINT('',(-129.292233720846,23.7569688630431,-3.43703261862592));
#581=CARTESIAN_POINT('',(-129.218383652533,23.818297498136,-2.98329397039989));
#582=CARTESIAN_POINT('',(-129.107044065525,23.9108516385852,-2.10885007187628));
#583=CARTESIAN_POINT('',(-129.066948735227,23.9442330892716,-1.68870802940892));
#584=CARTESIAN_POINT('',(-129.026806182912,23.9776651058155,-1.05648771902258));
#585=CARTESIAN_POINT('',(-129.016758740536,23.9860357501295,-0.845418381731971));
#586=CARTESIAN_POINT('',(-129.003354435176,23.9972045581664,-0.422907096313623));
#587=CARTESIAN_POINT('',(-128.999997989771,24.0000023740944,-0.211465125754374));
#588=CARTESIAN_POINT('',(-129.,24.,0.));
#589=B_SPLINE_CURVE_WITH_KNOTS('',3,(#537,#538,#539,#540,#541,#542,#543,#544,#545,#546,#547,
#548,#549,#550,#551,#552,#553,#554,#555,#556,#557,#558,#559,#560,#561,#562,#563,#564,#565,#566,
#567,#568,#569,#570,#571,#572,#573,#574,#575,#576,#577,#578,#579,#580,#581,#582,#583,#584,#585,
#586,#587,#588),.UNSPECIFIED.,.F.,.F.,(4,2,2,2,2,2,2,2,2,2,2,2,2,2,2,2,2,2,2,2,2,2,2,2,2,4),(0.,
0.535852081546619,1.0716281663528,2.14088197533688,3.19447739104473,4.2486570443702,
5.72111734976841,7.19417070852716,8.67884470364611,10.1634884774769,12.305174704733,
14.4477682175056,16.5857321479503,18.7228811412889,20.4074241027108,22.0919149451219,
23.7749050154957,24.6163228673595,25.4579608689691,26.8505788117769,28.2429292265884,
29.6330883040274,31.0226576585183,32.2912508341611,32.9255156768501,33.5598201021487),.UNSPECIFIED.);
#590=CARTESIAN_POINT('',(-149.,13.2664991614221,-19.9999999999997));
#591=VERTEX_POINT('',#590);
#592=EDGE_CURVE('E55',#591,#534,#589,.T.);
#593=ORIENTED_EDGE('',*,*,#592,.F.);
#594=DIRECTION('',(1.,0.,0.));
#595=VECTOR('',#594,1.);
#596=CARTESIAN_POINT('',(0.,13.2664991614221,-19.9999999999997));
#597=LINE('',#596,#595);
#598=CARTESIAN_POINT('',(-264.,13.2664991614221,-19.9999999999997));
#599=VERTEX_POINT('',#598);
#600=EDGE_CURVE('E378',#599,#591,#597,.T.);
#601=ORIENTED_EDGE('',*,*,#600,.F.);
#602=CARTESIAN_POINT('',(-264.,0.,0.));
#603=DIRECTION('',(1.,0.,0.));
#604=DIRECTION('',(0.,0.,-1.));
#605=AXIS2_PLACEMENT_3D('',#602,#603,#604);
#606=CIRCLE('',#605,24.);
#607=EDGE_CURVE('E200',#462,#599,#606,.T.);
#608=ORIENTED_EDGE('',*,*,#607,.F.);
#609=EDGE_LOOP('',(#464,#521,#527,#528,#536,#593,#601,#608));
#610=FACE_BOUND('',#609,.T.);
#611=ADVANCED_FACE('F284',(#454,#610),#289,.F.);
#612=CARTESIAN_POINT('',(-264.,-46.2222222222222,3.22768052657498E-13));
#613=DIRECTION('',(-1.,0.,0.));
#614=DIRECTION('',(0.,0.,1.));
#615=AXIS2_PLACEMENT_3D('',#612,#613,#614);
#616=PLANE('',#615);
#617=DIRECTION('',(0.,1.,0.));
#618=VECTOR('',#617,1.);
#619=CARTESIAN_POINT('',(-264.,43.6816859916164,-38.));
#620=LINE('',#619,#618);
#621=CARTESIAN_POINT('',(-264.,-26.3152774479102,-38.));
#622=VERTEX_POINT('',#621);
#623=CARTESIAN_POINT('',(-264.,26.3152774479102,-38.));
#624=VERTEX_POINT('',#623);
#625=EDGE_CURVE('E180',#622,#624,#620,.T.);
#626=ORIENTED_EDGE('',*,*,#625,.F.);
#627=CARTESIAN_POINT('',(-264.,0.,0.));
#628=DIRECTION('',(1.,0.,0.));
#629=DIRECTION('',(0.,0.,-1.));
#630=AXIS2_PLACEMENT_3D('',#627,#628,#629);
#631=CIRCLE('',#630,46.2222222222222);
#632=CARTESIAN_POINT('',(-264.,-41.6712590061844,-19.9999999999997));
#633=VERTEX_POINT('',#632);
#634=EDGE_CURVE('E192',#633,#622,#631,.T.);
#635=ORIENTED_EDGE('',*,*,#634,.F.);
#636=DIRECTION('',(0.,1.,0.));
#637=VECTOR('',#636,1.);
#638=CARTESIAN_POINT('',(-264.,-46.2222222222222,-19.9999999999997));
#639=LINE('',#638,#637);
#640=EDGE_CURVE('E303',#633,#462,#639,.T.);
#641=ORIENTED_EDGE('',*,*,#640,.T.);
#642=ORIENTED_EDGE('',*,*,#607,.T.);
#643=CARTESIAN_POINT('',(-264.,41.6712590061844,-19.9999999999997));
#644=VERTEX_POINT('',#643);
#645=EDGE_CURVE('E301',#599,#644,#639,.T.);
#646=ORIENTED_EDGE('',*,*,#645,.T.);
#647=EDGE_CURVE('E194',#624,#644,#631,.T.);
#648=ORIENTED_EDGE('',*,*,#647,.F.);
#649=EDGE_LOOP('',(#626,#635,#641,#642,#646,#648));
#650=FACE_BOUND('',#649,.T.);
#651=ADVANCED_FACE('F190',(#650),#616,.T.);
#652=CARTESIAN_POINT('',(0.,0.,0.));
#653=DIRECTION('',(1.,0.,0.));
#654=DIRECTION('',(0.,0.,-1.));
#655=AXIS2_PLACEMENT_3D('',#652,#653,#654);
#656=CYLINDRICAL_SURFACE('',#655,46.2222222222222);
#657=DIRECTION('',(1.,0.,0.));
#658=VECTOR('',#657,1.);
#659=CARTESIAN_POINT('',(0.,-26.3152774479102,-38.));
#660=LINE('',#659,#658);
#661=CARTESIAN_POINT('',(-219.,-26.3152774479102,-38.));
#662=VERTEX_POINT('',#661);
#663=EDGE_CURVE('E176',#662,#622,#660,.F.);
#664=ORIENTED_EDGE('',*,*,#663,.F.);
#665=CARTESIAN_POINT('',(-219.,0.,0.));
#666=DIRECTION('',(-1.,0.,0.));
#667=DIRECTION('',(0.,0.,1.));
#668=AXIS2_PLACEMENT_3D('',#665,#666,#667);
#669=CIRCLE('',#668,46.2222222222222);
#670=CARTESIAN_POINT('',(-219.,26.3152774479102,-38.));
#671=VERTEX_POINT('',#670);
#672=EDGE_CURVE('E11',#662,#671,#669,.F.);
#673=ORIENTED_EDGE('',*,*,#672,.T.);
#674=DIRECTION('',(1.,0.,0.));
#675=VECTOR('',#674,1.);
#676=CARTESIAN_POINT('',(0.,26.3152774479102,-38.));
#677=LINE('',#676,#675);
#678=EDGE_CURVE('E185',#624,#671,#677,.T.);
#679=ORIENTED_EDGE('',*,*,#678,.F.);
#680=ORIENTED_EDGE('',*,*,#647,.T.);
#681=DIRECTION('',(1.,0.,0.));
#682=VECTOR('',#681,1.);
#683=CARTESIAN_POINT('',(0.,41.6712590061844,-19.9999999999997));
#684=LINE('',#683,#682);
#685=CARTESIAN_POINT('',(-212.,41.6712590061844,-19.9999999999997));
#686=VERTEX_POINT('',#685);
#687=EDGE_CURVE('E323',#686,#644,#684,.F.);
#688=ORIENTED_EDGE('',*,*,#687,.F.);
#689=CARTESIAN_POINT('',(-212.,0.,0.));
#690=DIRECTION('',(1.,0.,0.));
#691=DIRECTION('',(0.,0.,-1.));
#692=AXIS2_PLACEMENT_3D('',#689,#690,#691);
#693=CIRCLE('',#692,46.2222222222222);
#694=CARTESIAN_POINT('',(-212.,-41.6712590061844,-19.9999999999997));
#695=VERTEX_POINT('',#694);
#696=EDGE_CURVE('E205',#695,#686,#693,.T.);
#697=ORIENTED_EDGE('',*,*,#696,.F.);
#698=DIRECTION('',(1.,0.,0.));
#699=VECTOR('',#698,1.);
#700=CARTESIAN_POINT('',(0.,-41.6712590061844,-19.9999999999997));
#701=LINE('',#700,#699);
#702=EDGE_CURVE('E199',#633,#695,#701,.T.);
#703=ORIENTED_EDGE('',*,*,#702,.F.);
#704=ORIENTED_EDGE('',*,*,#634,.T.);
#705=EDGE_LOOP('',(#664,#673,#679,#680,#688,#697,#703,#704));
#706=FACE_BOUND('',#705,.T.);
#707=ADVANCED_FACE('F197',(#706),#656,.T.);
#708=CARTESIAN_POINT('',(-129.,0.,0.));
#709=DIRECTION('',(-1.,0.,0.));
#710=DIRECTION('',(0.,0.,1.));
#711=AXIS2_PLACEMENT_3D('',#708,#709,#710);
#712=CONICAL_SURFACE('',#711,37.,0.110657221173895);
#713=CARTESIAN_POINT('',(-274.995920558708,49.320955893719,-19.9999999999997));
#714=CARTESIAN_POINT('',(-268.379183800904,48.5275800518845,-19.9999999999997));
#715=CARTESIAN_POINT('',(-261.762757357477,47.7316078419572,-19.9999999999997));
#716=CARTESIAN_POINT('',(-248.530652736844,46.1334638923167,-19.9999999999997));
#717=CARTESIAN_POINT('',(-241.914974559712,45.3312921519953,-19.9999999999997));
#718=CARTESIAN_POINT('',(-228.68415329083,43.7197008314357,-19.9999999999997));
#719=CARTESIAN_POINT('',(-222.069010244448,42.9102808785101,-19.9999999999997));
#720=CARTESIAN_POINT('',(-208.839770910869,41.2829084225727,-19.9999999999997));
#721=CARTESIAN_POINT('',(-202.225674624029,40.4649559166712,-19.9999999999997));
#722=CARTESIAN_POINT('',(-188.998754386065,38.8188512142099,-19.9999999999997));
#723=CARTESIAN_POINT('',(-182.385930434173,37.9906990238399,-19.9999999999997));
#724=CARTESIAN_POINT('',(-169.161850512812,36.3220228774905,-19.9999999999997));
#725=CARTESIAN_POINT('',(-162.550594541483,35.4814989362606,-19.9999999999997));
#726=CARTESIAN_POINT('',(-149.330263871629,33.7852470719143,-19.9999999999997));
#727=CARTESIAN_POINT('',(-142.721189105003,32.929519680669,-19.9999999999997));
#728=CARTESIAN_POINT('',(-132.809447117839,31.6315262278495,-19.9999999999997));
#729=CARTESIAN_POINT('',(-129.505836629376,31.1964602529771,-19.9999999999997));
#730=CARTESIAN_POINT('',(-122.899338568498,30.3208759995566,-19.9999999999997));
#731=CARTESIAN_POINT('',(-119.596450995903,29.8803577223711,-19.9999999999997));
#732=CARTESIAN_POINT('',(-112.991281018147,28.9930828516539,-19.9999999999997));
#733=CARTESIAN_POINT('',(-109.688998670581,28.5463258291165,-19.9999999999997));
#734=CARTESIAN_POINT('',(-103.085407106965,27.6456799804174,-19.9999999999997));
#735=CARTESIAN_POINT('',(-99.7840978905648,27.1917911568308,-19.9999999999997));
#736=CARTESIAN_POINT('',(-93.182666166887,26.2757542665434,-19.9999999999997));
#737=CARTESIAN_POINT('',(-89.8825436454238,25.8136063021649,-19.9999999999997));
#738=CARTESIAN_POINT('',(-83.2836618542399,24.8796321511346,-19.9999999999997));
#739=CARTESIAN_POINT('',(-79.9849025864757,24.4078059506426,-19.9999999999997));
#740=CARTESIAN_POINT('',(-73.3887628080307,23.45263832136,-19.9999999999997));
#741=CARTESIAN_POINT('',(-70.0913824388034,22.9692959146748,-19.9999999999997));
#742=CARTESIAN_POINT('',(-63.4986808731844,21.9888185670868,-19.9999999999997));
#743=CARTESIAN_POINT('',(-60.2033596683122,21.4916836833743,-19.9999999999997));
#744=CARTESIAN_POINT('',(-55.2622572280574,20.7332774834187,-19.9999999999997));
#745=CARTESIAN_POINT('',(-53.6155011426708,20.4783525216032,-19.9999999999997));
#746=CARTESIAN_POINT('',(-50.3227302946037,19.9637647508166,-19.9999999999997));
#747=CARTESIAN_POINT('',(-48.6767155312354,19.7041019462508,-19.9999999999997));
#748=CARTESIAN_POINT('',(-45.3855083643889,19.1794654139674,-19.9999999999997));
#749=CARTESIAN_POINT('',(-43.740315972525,18.9144916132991,-19.9999999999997));
#750=CARTESIAN_POINT('',(-40.4509094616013,18.3785094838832,-19.9999999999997));
#751=CARTESIAN_POINT('',(-38.8066953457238,18.1075011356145,-19.9999999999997));
#752=CARTESIAN_POINT('',(-37.1630423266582,17.8331128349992,-19.9999999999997));
#753=B_SPLINE_CURVE_WITH_KNOTS('',3,(#713,#714,#715,#716,#717,#718,#719,#720,#721,#722,#723,
#724,#725,#726,#727,#728,#729,#730,#731,#732,#733,#734,#735,#736,#737,#738,#739,#740,#741,#742,
#743,#744,#745,#746,#747,#748,#749,#750,#751,#752),.UNSPECIFIED.,.F.,.F.,(4,2,2,2,2,2,2,2,2,2,2,
2,2,2,2,2,2,2,2,4),(0.,19.9923958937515,39.9847937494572,59.978225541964,79.9716641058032,
99.965090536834,119.958493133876,139.951197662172,149.947599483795,159.943998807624,
169.94108894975,179.938175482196,189.935138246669,199.932115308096,209.929944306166,
219.927731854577,224.926839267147,229.925942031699,234.925113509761,239.924301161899),.UNSPECIFIED.);
#754=CARTESIAN_POINT('',(-149.,33.7399276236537,-19.9999999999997));
#755=VERTEX_POINT('',#754);
#756=EDGE_CURVE('E41',#755,#686,#753,.F.);
#757=ORIENTED_EDGE('',*,*,#756,.F.);
#758=CARTESIAN_POINT('',(-129.000000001,36.9999999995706,0.000200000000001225));
#759=CARTESIAN_POINT('',(-128.999996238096,37.0000047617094,-0.269025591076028));
#760=CARTESIAN_POINT('',(-129.005431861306,36.9976669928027,-0.538215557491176));
#761=CARTESIAN_POINT('',(-129.027155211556,36.9883451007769,-1.07606567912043));
#762=CARTESIAN_POINT('',(-129.043442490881,36.9813611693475,-1.34472585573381));
#763=CARTESIAN_POINT('',(-129.108517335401,36.9535086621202,-2.14894641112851));
#764=CARTESIAN_POINT('',(-129.173517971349,36.9257392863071,-2.68305990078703));
#765=CARTESIAN_POINT('',(-129.345684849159,36.8528123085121,-3.74085307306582));
#766=CARTESIAN_POINT('',(-129.45267454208,36.8077275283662,-4.26456691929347));
#767=CARTESIAN_POINT('',(-129.707733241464,36.7015426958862,-5.3002684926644));
#768=CARTESIAN_POINT('',(-129.855804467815,36.6404417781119,-5.81225558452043));
#769=CARTESIAN_POINT('',(-130.191428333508,36.5041402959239,-6.82053753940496));
#770=CARTESIAN_POINT('',(-130.378939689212,36.4289544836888,-7.31684819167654));
#771=CARTESIAN_POINT('',(-130.791979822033,36.2666389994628,-8.29144544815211));
#772=CARTESIAN_POINT('',(-131.017510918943,36.1795085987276,-8.76973095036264));
#773=CARTESIAN_POINT('',(-131.383082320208,36.0417429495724,-9.47174678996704));
#774=CARTESIAN_POINT('',(-131.509575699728,35.9946100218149,-9.70332779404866));
#775=CARTESIAN_POINT('',(-131.771395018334,35.8983515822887,-10.1609367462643));
#776=CARTESIAN_POINT('',(-131.906718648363,35.8492265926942,-10.3869661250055));
#777=CARTESIAN_POINT('',(-132.325693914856,35.6993635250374,-11.0564310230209));
#778=CARTESIAN_POINT('',(-132.622357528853,35.5961344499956,-11.4912578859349));
#779=CARTESIAN_POINT('',(-133.264423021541,35.3807651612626,-12.3570514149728));
#780=CARTESIAN_POINT('',(-133.611534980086,35.2684386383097,-12.7867004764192));
#781=CARTESIAN_POINT('',(-134.340067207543,35.0435619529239,-13.6158332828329));
#782=CARTESIAN_POINT('',(-134.721488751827,34.9310117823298,-14.0153159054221));
#783=CARTESIAN_POINT('',(-135.516652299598,34.7096321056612,-14.7818920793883));
#784=CARTESIAN_POINT('',(-135.930396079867,34.6008028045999,-15.1489838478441));
#785=CARTESIAN_POINT('',(-136.788299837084,34.3909335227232,-15.8486880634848));
#786=CARTESIAN_POINT('',(-137.232474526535,34.2898973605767,-16.1812836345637));
#787=CARTESIAN_POINT('',(-138.16457516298,34.0966104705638,-16.8203375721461));
#788=CARTESIAN_POINT('',(-138.653482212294,34.0047835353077,-17.1254969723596));
#789=CARTESIAN_POINT('',(-139.657858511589,33.838751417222,-17.6934159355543));
#790=CARTESIAN_POINT('',(-140.173312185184,33.764536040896,-17.9561999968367));
#791=CARTESIAN_POINT('',(-141.226683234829,33.6381350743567,-18.4366543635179));
#792=CARTESIAN_POINT('',(-141.764571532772,33.5859218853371,-18.6543810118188));
#793=CARTESIAN_POINT('',(-142.858859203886,33.5072285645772,-19.0426665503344));
#794=CARTESIAN_POINT('',(-143.415252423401,33.4807399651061,-19.2132409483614));
#795=CARTESIAN_POINT('',(-144.388100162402,33.4596336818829,-19.4656069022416));
#796=CARTESIAN_POINT('',(-144.80146563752,33.4583081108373,-19.5589279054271));
#797=CARTESIAN_POINT('',(-145.633001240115,33.4714436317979,-19.7190902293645));
#798=CARTESIAN_POINT('',(-146.051170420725,33.4859016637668,-19.7859366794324));
#799=CARTESIAN_POINT('',(-146.891139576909,33.5309674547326,-19.8930221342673));
#800=CARTESIAN_POINT('',(-147.312946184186,33.5616173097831,-19.9331911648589));
#801=CARTESIAN_POINT('',(-148.156912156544,33.6388725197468,-19.9867084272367));
#802=CARTESIAN_POINT('',(-148.579071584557,33.6854819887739,-20.0000497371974));
#803=CARTESIAN_POINT('',(-149.0002,33.7399534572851,-19.9999999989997));
#804=B_SPLINE_CURVE_WITH_KNOTS('',3,(#758,#759,#760,#761,#762,#763,#764,#765,#766,#767,#768,
#769,#770,#771,#772,#773,#774,#775,#776,#777,#778,#779,#780,#781,#782,#783,#784,#785,#786,#787,
#788,#789,#790,#791,#792,#793,#794,#795,#796,#797,#798,#799,#800,#801,#802,#803),.UNSPECIFIED.,
.F.,.F.,(4,2,2,2,2,2,2,2,2,2,2,2,2,2,2,2,2,2,2,2,2,2,4),(0.,0.80754085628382,1.61504839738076,
3.22912749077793,4.83649144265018,6.44394226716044,8.0497188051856,9.65559335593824,
10.4595689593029,11.2633351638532,12.8708176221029,14.5599392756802,16.2491237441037,
17.9384011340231,19.6285010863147,21.3769563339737,23.124397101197,24.8696393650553,
26.6143069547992,27.884551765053,29.1545503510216,30.4278670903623,31.7015123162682),.UNSPECIFIED.);
#805=CARTESIAN_POINT('',(-129.,37.,0.));
#806=VERTEX_POINT('',#805);
#807=EDGE_CURVE('E270',#806,#755,#804,.T.);
#808=ORIENTED_EDGE('',*,*,#807,.F.);
#809=CARTESIAN_POINT('',(-129.,0.,0.));
#810=DIRECTION('',(1.,0.,0.));
#811=DIRECTION('',(0.,0.,-1.));
#812=AXIS2_PLACEMENT_3D('',#809,#810,#811);
#813=CIRCLE('',#812,37.);
#814=CARTESIAN_POINT('',(-129.,-37.,2.58369619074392E-13));
#815=VERTEX_POINT('',#814);
#816=EDGE_CURVE('E362',#815,#806,#813,.T.);
#817=ORIENTED_EDGE('',*,*,#816,.F.);
#818=CARTESIAN_POINT('',(-149.0002,-33.7399534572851,-19.9999999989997));
#819=CARTESIAN_POINT('',(-148.751149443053,-33.707778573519,-20.00000371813));
#820=CARTESIAN_POINT('',(-148.501777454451,-33.6783184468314,-19.9953519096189));
#821=CARTESIAN_POINT('',(-148.002793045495,-33.6249229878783,-19.9766844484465));
#822=CARTESIAN_POINT('',(-147.753180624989,-33.6009876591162,-19.9626687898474));
#823=CARTESIAN_POINT('',(-147.004805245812,-33.5376303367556,-19.9065132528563));
#824=CARTESIAN_POINT('',(-146.5062854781,-33.5066286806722,-19.8502649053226));
#825=CARTESIAN_POINT('',(-145.516617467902,-33.4672786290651,-19.7006430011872));
#826=CARTESIAN_POINT('',(-145.025444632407,-33.4588158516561,-19.6074596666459));
#827=CARTESIAN_POINT('',(-144.051559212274,-33.4634310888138,-19.3845925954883));
#828=CARTESIAN_POINT('',(-143.568846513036,-33.4765088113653,-19.2549093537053));
#829=CARTESIAN_POINT('',(-142.615554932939,-33.5226860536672,-18.9601613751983));
#830=CARTESIAN_POINT('',(-142.144971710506,-33.5557783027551,-18.7951095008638));
#831=CARTESIAN_POINT('',(-141.218797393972,-33.6398657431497,-18.4309666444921));
#832=CARTESIAN_POINT('',(-140.76320774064,-33.6908626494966,-18.2318724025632));
#833=CARTESIAN_POINT('',(-139.869312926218,-33.808266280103,-17.8010384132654));
#834=CARTESIAN_POINT('',(-139.431023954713,-33.8746870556,-17.5692689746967));
#835=CARTESIAN_POINT('',(-138.574409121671,-34.0200984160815,-17.0748833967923));
#836=CARTESIAN_POINT('',(-138.156083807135,-34.0990893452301,-16.8122664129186));
#837=CARTESIAN_POINT('',(-137.321396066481,-34.2708025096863,-16.2443012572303));
#838=CARTESIAN_POINT('',(-136.906126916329,-34.3640068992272,-15.9374927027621));
#839=CARTESIAN_POINT('',(-136.101388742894,-34.5576522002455,-15.2935131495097));
#840=CARTESIAN_POINT('',(-135.711930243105,-34.65809602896,-14.9563298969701));
#841=CARTESIAN_POINT('',(-134.960517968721,-34.8629012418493,-14.2533416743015));
#842=CARTESIAN_POINT('',(-134.59857713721,-34.9672644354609,-13.8875233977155));
#843=CARTESIAN_POINT('',(-133.90416311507,-35.1766011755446,-13.1293540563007));
#844=CARTESIAN_POINT('',(-133.571680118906,-35.28157450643,-12.7370118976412));
#845=CARTESIAN_POINT('',(-132.904263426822,-35.5000208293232,-11.8848636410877));
#846=CARTESIAN_POINT('',(-132.57274118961,-35.6132283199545,-11.4223001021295));
#847=CARTESIAN_POINT('',(-132.105516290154,-35.7778617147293,-10.7078223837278));
#848=CARTESIAN_POINT('',(-131.954774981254,-35.8318801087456,-10.4662069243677));
#849=CARTESIAN_POINT('',(-131.663499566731,-35.9377662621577,-9.97632117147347));
#850=CARTESIAN_POINT('',(-131.522968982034,-35.9896332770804,-9.72804862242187));
#851=CARTESIAN_POINT('',(-131.117489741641,-36.1411976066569,-8.97446076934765));
#852=CARTESIAN_POINT('',(-130.868263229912,-36.2369975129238,-8.45977860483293));
#853=CARTESIAN_POINT('',(-130.414121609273,-36.414865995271,-7.40895596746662));
#854=CARTESIAN_POINT('',(-130.209201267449,-36.4969361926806,-6.87281803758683));
#855=CARTESIAN_POINT('',(-129.943173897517,-36.6049537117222,-6.07523063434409));
#856=CARTESIAN_POINT('',(-129.863863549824,-36.6374011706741,-5.82060936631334));
#857=CARTESIAN_POINT('',(-129.715398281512,-36.6984972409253,-5.30804188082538));
#858=CARTESIAN_POINT('',(-129.646240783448,-36.7271468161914,-5.05009652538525));
#859=CARTESIAN_POINT('',(-129.4542380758,-36.8070690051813,-4.27183978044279));
#860=CARTESIAN_POINT('',(-129.346827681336,-36.8523294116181,-3.7470029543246));
#861=CARTESIAN_POINT('',(-129.17406366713,-36.9255069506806,-2.68727894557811));
#862=CARTESIAN_POINT('',(-129.108863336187,-36.9533608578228,-2.15236231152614));
#863=CARTESIAN_POINT('',(-129.043583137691,-36.9813008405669,-1.34689159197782));
#864=CARTESIAN_POINT('',(-129.027243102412,-36.9883073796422,-1.07779967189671));
#865=CARTESIAN_POINT('',(-129.005449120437,-36.9976595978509,-0.539082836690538));
#866=CARTESIAN_POINT('',(-128.999995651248,-37.0000050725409,-0.26945789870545));
#867=CARTESIAN_POINT('',(-129.000000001,-36.9999999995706,0.000200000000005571));
#868=B_SPLINE_CURVE_WITH_KNOTS('',3,(#818,#819,#820,#821,#822,#823,#824,#825,#826,#827,#828,
#829,#830,#831,#832,#833,#834,#835,#836,#837,#838,#839,#840,#841,#842,#843,#844,#845,#846,#847,
#848,#849,#850,#851,#852,#853,#854,#855,#856,#857,#858,#859,#860,#861,#862,#863,#864,#865,#866,
#867),.UNSPECIFIED.,.F.,.F.,(4,2,2,2,2,2,2,2,2,2,2,2,2,2,2,2,2,2,2,2,2,2,2,2,4),(0.,
0.753242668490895,1.50648581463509,3.0123128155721,4.5104832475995,6.00863336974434,
7.50623958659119,9.00398929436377,10.5031088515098,12.0022694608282,13.5746336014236,
15.1476349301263,16.7213716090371,18.2945824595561,20.0330541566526,20.9024106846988,
21.7720655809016,23.5092032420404,25.2461356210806,26.0518932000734,26.8574458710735,
28.468218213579,30.0848078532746,30.8936151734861,31.7024579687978),.UNSPECIFIED.);
#869=CARTESIAN_POINT('',(-149.,-33.7399276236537,-19.9999999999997));
#870=VERTEX_POINT('',#869);
#871=EDGE_CURVE('E262',#870,#815,#868,.T.);
#872=ORIENTED_EDGE('',*,*,#871,.F.);
#873=CARTESIAN_POINT('',(-274.995920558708,-49.320955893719,-19.9999999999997));
#874=CARTESIAN_POINT('',(-268.379183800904,-48.5275800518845,-19.9999999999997));
#875=CARTESIAN_POINT('',(-261.762757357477,-47.7316078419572,-19.9999999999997));
#876=CARTESIAN_POINT('',(-248.530652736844,-46.1334638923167,-19.9999999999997));
#877=CARTESIAN_POINT('',(-241.914974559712,-45.3312921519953,-19.9999999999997));
#878=CARTESIAN_POINT('',(-228.68415329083,-43.7197008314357,-19.9999999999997));
#879=CARTESIAN_POINT('',(-222.069010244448,-42.9102808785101,-19.9999999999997));
#880=CARTESIAN_POINT('',(-208.839770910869,-41.2829084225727,-19.9999999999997));
#881=CARTESIAN_POINT('',(-202.225674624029,-40.4649559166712,-19.9999999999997));
#882=CARTESIAN_POINT('',(-188.998754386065,-38.8188512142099,-19.9999999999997));
#883=CARTESIAN_POINT('',(-182.385930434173,-37.9906990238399,-19.9999999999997));
#884=CARTESIAN_POINT('',(-169.161850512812,-36.3220228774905,-19.9999999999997));
#885=CARTESIAN_POINT('',(-162.550594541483,-35.4814989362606,-19.9999999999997));
#886=CARTESIAN_POINT('',(-149.330263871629,-33.7852470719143,-19.9999999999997));
#887=CARTESIAN_POINT('',(-142.721189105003,-32.929519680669,-19.9999999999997));
#888=CARTESIAN_POINT('',(-132.809447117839,-31.6315262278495,-19.9999999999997));
#889=CARTESIAN_POINT('',(-129.505836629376,-31.1964602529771,-19.9999999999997));
#890=CARTESIAN_POINT('',(-122.899338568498,-30.3208759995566,-19.9999999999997));
#891=CARTESIAN_POINT('',(-119.596450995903,-29.8803577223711,-19.9999999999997));
#892=CARTESIAN_POINT('',(-112.991281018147,-28.9930828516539,-19.9999999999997));
#893=CARTESIAN_POINT('',(-109.688998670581,-28.5463258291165,-19.9999999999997));
#894=CARTESIAN_POINT('',(-103.085407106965,-27.6456799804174,-19.9999999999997));
#895=CARTESIAN_POINT('',(-99.7840978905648,-27.1917911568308,-19.9999999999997));
#896=CARTESIAN_POINT('',(-93.182666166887,-26.2757542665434,-19.9999999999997));
#897=CARTESIAN_POINT('',(-89.8825436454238,-25.8136063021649,-19.9999999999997));
#898=CARTESIAN_POINT('',(-83.2836618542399,-24.8796321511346,-19.9999999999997));
#899=CARTESIAN_POINT('',(-79.9849025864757,-24.4078059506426,-19.9999999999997));
#900=CARTESIAN_POINT('',(-73.3887628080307,-23.45263832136,-19.9999999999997));
#901=CARTESIAN_POINT('',(-70.0913824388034,-22.9692959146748,-19.9999999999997));
#902=CARTESIAN_POINT('',(-63.4986808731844,-21.9888185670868,-19.9999999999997));
#903=CARTESIAN_POINT('',(-60.2033596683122,-21.4916836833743,-19.9999999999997));
#904=CARTESIAN_POINT('',(-55.2622572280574,-20.7332774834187,-19.9999999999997));
#905=CARTESIAN_POINT('',(-53.6155011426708,-20.4783525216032,-19.9999999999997));
#906=CARTESIAN_POINT('',(-50.3227302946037,-19.9637647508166,-19.9999999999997));
#907=CARTESIAN_POINT('',(-48.6767155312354,-19.7041019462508,-19.9999999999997));
#908=CARTESIAN_POINT('',(-45.3855083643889,-19.1794654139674,-19.9999999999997));
#909=CARTESIAN_POINT('',(-43.740315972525,-18.9144916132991,-19.9999999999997));
#910=CARTESIAN_POINT('',(-40.4509094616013,-18.3785094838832,-19.9999999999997));
#911=CARTESIAN_POINT('',(-38.8066953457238,-18.1075011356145,-19.9999999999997));
#912=CARTESIAN_POINT('',(-37.1630423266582,-17.8331128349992,-19.9999999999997));
#913=B_SPLINE_CURVE_WITH_KNOTS('',3,(#873,#874,#875,#876,#877,#878,#879,#880,#881,#882,#883,
#884,#885,#886,#887,#888,#889,#890,#891,#892,#893,#894,#895,#896,#897,#898,#899,#900,#901,#902,
#903,#904,#905,#906,#907,#908,#909,#910,#911,#912),.UNSPECIFIED.,.F.,.F.,(4,2,2,2,2,2,2,2,2,2,2,
2,2,2,2,2,2,2,2,4),(0.,19.9923958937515,39.9847937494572,59.978225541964,79.9716641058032,
99.965090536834,119.958493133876,139.951197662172,149.947599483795,159.943998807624,
169.94108894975,179.938175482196,189.935138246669,199.932115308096,209.929944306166,
219.927731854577,224.926839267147,229.925942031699,234.925113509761,239.924301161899),.UNSPECIFIED.);
#914=EDGE_CURVE('E227',#695,#870,#913,.T.);
#915=ORIENTED_EDGE('',*,*,#914,.F.);
#916=ORIENTED_EDGE('',*,*,#696,.T.);
#917=EDGE_LOOP('',(#757,#808,#817,#872,#915,#916));
#918=FACE_BOUND('',#917,.T.);
#919=ADVANCED_FACE('F237',(#918),#712,.T.);
#920=CARTESIAN_POINT('',(0.,0.,0.));
#921=DIRECTION('',(1.,0.,0.));
#922=DIRECTION('',(0.,0.,-1.));
#923=AXIS2_PLACEMENT_3D('',#920,#921,#922);
#924=CYLINDRICAL_SURFACE('',#923,37.);
#925=CARTESIAN_POINT('',(-25.,0.,0.));
#926=DIRECTION('',(1.,0.,0.));
#927=DIRECTION('',(0.,0.,-1.));
#928=AXIS2_PLACEMENT_3D('',#925,#926,#927);
#929=CIRCLE('',#928,37.);
#930=CARTESIAN_POINT('',(-25.,-37.,2.58369619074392E-13));
#931=VERTEX_POINT('',#930);
#932=CARTESIAN_POINT('',(-25.,37.,0.));
#933=VERTEX_POINT('',#932);
#934=EDGE_CURVE('E361',#931,#933,#929,.T.);
#935=ORIENTED_EDGE('',*,*,#934,.F.);
#936=DIRECTION('',(-1.,0.,0.));
#937=VECTOR('',#936,1.);
#938=CARTESIAN_POINT('',(-129.,-37.,2.58369619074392E-13));
#939=LINE('',#938,#937);
#940=EDGE_CURVE('E329',#931,#815,#939,.T.);
#941=ORIENTED_EDGE('',*,*,#940,.T.);
#942=ORIENTED_EDGE('',*,*,#816,.T.);
#943=DIRECTION('',(-1.,0.,0.));
#944=VECTOR('',#943,1.);
#945=CARTESIAN_POINT('',(-129.,37.,0.));
#946=LINE('',#945,#944);
#947=EDGE_CURVE('E392',#933,#806,#946,.T.);
#948=ORIENTED_EDGE('',*,*,#947,.F.);
#949=EDGE_LOOP('',(#935,#941,#942,#948));
#950=FACE_BOUND('',#949,.T.);
#951=ADVANCED_FACE('F431',(#950),#924,.T.);
#952=CARTESIAN_POINT('',(-25.,-37.,2.58369619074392E-13));
#953=DIRECTION('',(1.,0.,0.));
#954=DIRECTION('',(0.,0.,-1.));
#955=AXIS2_PLACEMENT_3D('',#952,#953,#954);
#956=PLANE('',#955);
#957=CARTESIAN_POINT('',(-25.,0.,0.));
#958=DIRECTION('',(1.,0.,0.));
#959=DIRECTION('',(0.,0.,-1.));
#960=AXIS2_PLACEMENT_3D('',#957,#958,#959);
#961=CIRCLE('',#960,36.);
#962=CARTESIAN_POINT('',(-25.,-36.,2.51386656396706E-13));
#963=VERTEX_POINT('',#962);
#964=CARTESIAN_POINT('',(-25.,36.,0.));
#965=VERTEX_POINT('',#964);
#966=EDGE_CURVE('E359',#963,#965,#961,.T.);
#967=ORIENTED_EDGE('',*,*,#966,.F.);
#968=DIRECTION('',(0.,-1.,0.));
#969=VECTOR('',#968,1.);
#970=CARTESIAN_POINT('',(-25.,-37.,2.58369619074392E-13));
#971=LINE('',#970,#969);
#972=EDGE_CURVE('E334',#963,#931,#971,.T.);
#973=ORIENTED_EDGE('',*,*,#972,.T.);
#974=ORIENTED_EDGE('',*,*,#934,.T.);
#975=DIRECTION('',(0.,1.,0.));
#976=VECTOR('',#975,1.);
#977=CARTESIAN_POINT('',(-25.,37.,0.));
#978=LINE('',#977,#976);
#979=EDGE_CURVE('E389',#965,#933,#978,.T.);
#980=ORIENTED_EDGE('',*,*,#979,.F.);
#981=EDGE_LOOP('',(#967,#973,#974,#980));
#982=FACE_BOUND('',#981,.T.);
#983=ADVANCED_FACE('F428',(#982),#956,.T.);
#984=CARTESIAN_POINT('',(0.,0.,0.));
#985=DIRECTION('',(1.,0.,0.));
#986=DIRECTION('',(0.,0.,-1.));
#987=AXIS2_PLACEMENT_3D('',#984,#985,#986);
#988=CYLINDRICAL_SURFACE('',#987,36.);
#989=CARTESIAN_POINT('',(0.,0.,0.));
#990=DIRECTION('',(1.,0.,0.));
#991=DIRECTION('',(0.,0.,-1.));
#992=AXIS2_PLACEMENT_3D('',#989,#990,#991);
#993=CIRCLE('',#992,36.);
#994=CARTESIAN_POINT('',(0.,-36.,2.51386656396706E-13));
#995=VERTEX_POINT('',#994);
#996=CARTESIAN_POINT('',(0.,36.,0.));
#997=VERTEX_POINT('',#996);
#998=EDGE_CURVE('E357',#995,#997,#993,.T.);
#999=ORIENTED_EDGE('',*,*,#998,.F.);
#1000=DIRECTION('',(-1.,0.,0.));
#1001=VECTOR('',#1000,1.);
#1002=CARTESIAN_POINT('',(0.,-36.,2.51386656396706E-13));
#1003=LINE('',#1002,#1001);
#1004=EDGE_CURVE('E423',#995,#963,#1003,.T.);
#1005=ORIENTED_EDGE('',*,*,#1004,.T.);
#1006=ORIENTED_EDGE('',*,*,#966,.T.);
#1007=DIRECTION('',(-1.,0.,0.));
#1008=VECTOR('',#1007,1.);
#1009=CARTESIAN_POINT('',(0.,36.,0.));
#1010=LINE('',#1009,#1008);
#1011=EDGE_CURVE('E386',#997,#965,#1010,.T.);
#1012=ORIENTED_EDGE('',*,*,#1011,.F.);
#1013=EDGE_LOOP('',(#999,#1005,#1006,#1012));
#1014=FACE_BOUND('',#1013,.T.);
#1015=ADVANCED_FACE('F437',(#1014),#988,.T.);
#1016=CARTESIAN_POINT('',(0.,-36.,2.51386656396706E-13));
#1017=DIRECTION('',(1.,0.,0.));
#1018=DIRECTION('',(0.,0.,-1.));
#1019=AXIS2_PLACEMENT_3D('',#1016,#1017,#1018);
#1020=PLANE('',#1019);
#1021=DIRECTION('',(0.,-1.,0.));
#1022=VECTOR('',#1021,1.);
#1023=CARTESIAN_POINT('',(0.,-36.,2.51386656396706E-13));
#1024=LINE('',#1023,#1022);
#1025=EDGE_CURVE('E420',#40,#995,#1024,.T.);
#1026=ORIENTED_EDGE('',*,*,#1025,.T.);
#1027=ORIENTED_EDGE('',*,*,#998,.T.);
#1028=DIRECTION('',(0.,1.,0.));
#1029=VECTOR('',#1028,1.);
#1030=CARTESIAN_POINT('',(0.,36.,0.));
#1031=LINE('',#1030,#1029);
#1032=EDGE_CURVE('E383',#49,#997,#1031,.T.);
#1033=ORIENTED_EDGE('',*,*,#1032,.F.);
#1034=ORIENTED_EDGE('',*,*,#50,.F.);
#1035=EDGE_LOOP('',(#1026,#1027,#1033,#1034));
#1036=FACE_BOUND('',#1035,.T.);
#1037=ADVANCED_FACE('F478',(#1036),#1020,.T.);
#1038=CARTESIAN_POINT('',(-78.,-27.5,1.92031473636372E-13));
#1039=DIRECTION('',(0.,0.,1.));
#1040=DIRECTION('',(-1.,0.,0.));
#1041=AXIS2_PLACEMENT_3D('',#1038,#1039,#1040);
#1042=PLANE('',#1041);
#1043=DIRECTION('',(0.,1.,0.));
#1044=VECTOR('',#1043,1.);
#1045=CARTESIAN_POINT('',(-129.,-46.2222222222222,0.));
#1046=LINE('',#1045,#1044);
#1047=EDGE_CURVE('E299',#815,#519,#1046,.T.);
#1048=ORIENTED_EDGE('',*,*,#1047,.F.);
#1049=ORIENTED_EDGE('',*,*,#940,.F.);
#1050=ORIENTED_EDGE('',*,*,#972,.F.);
#1051=ORIENTED_EDGE('',*,*,#1004,.F.);
#1052=ORIENTED_EDGE('',*,*,#1025,.F.);
#1053=ORIENTED_EDGE('',*,*,#41,.F.);
#1054=ORIENTED_EDGE('',*,*,#81,.F.);
#1055=ORIENTED_EDGE('',*,*,#113,.F.);
#1056=ORIENTED_EDGE('',*,*,#145,.F.);
#1057=ORIENTED_EDGE('',*,*,#177,.F.);
#1058=ORIENTED_EDGE('',*,*,#209,.F.);
#1059=ORIENTED_EDGE('',*,*,#241,.F.);
#1060=ORIENTED_EDGE('',*,*,#273,.F.);
#1061=ORIENTED_EDGE('',*,*,#526,.F.);
#1062=EDGE_LOOP('',(#1048,#1049,#1050,#1051,#1052,#1053,#1054,#1055,#1056,#1057,#1058,#1059,
#1060,#1061));
#1063=FACE_BOUND('',#1062,.T.);
#1064=ADVANCED_FACE('F325',(#1063),#1042,.T.);
#1065=CARTESIAN_POINT('',(-78.,27.5,0.));
#1066=DIRECTION('',(0.,0.,-1.));
#1067=DIRECTION('',(-1.,0.,0.));
#1068=AXIS2_PLACEMENT_3D('',#1065,#1066,#1067);
#1069=PLANE('',#1068);
#1070=ORIENTED_EDGE('',*,*,#947,.T.);
#1071=DIRECTION('',(0.,1.,0.));
#1072=VECTOR('',#1071,1.);
#1073=CARTESIAN_POINT('',(-129.,-46.2222222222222,0.));
#1074=LINE('',#1073,#1072);
#1075=EDGE_CURVE('E225',#806,#534,#1074,.F.);
#1076=ORIENTED_EDGE('',*,*,#1075,.T.);
#1077=ORIENTED_EDGE('',*,*,#535,.T.);
#1078=ORIENTED_EDGE('',*,*,#280,.T.);
#1079=ORIENTED_EDGE('',*,*,#248,.T.);
#1080=ORIENTED_EDGE('',*,*,#216,.T.);
#1081=ORIENTED_EDGE('',*,*,#184,.T.);
#1082=ORIENTED_EDGE('',*,*,#152,.T.);
#1083=ORIENTED_EDGE('',*,*,#120,.T.);
#1084=ORIENTED_EDGE('',*,*,#88,.T.);
#1085=ORIENTED_EDGE('',*,*,#56,.T.);
#1086=ORIENTED_EDGE('',*,*,#1032,.T.);
#1087=ORIENTED_EDGE('',*,*,#1011,.T.);
#1088=ORIENTED_EDGE('',*,*,#979,.T.);
#1089=EDGE_LOOP('',(#1070,#1076,#1077,#1078,#1079,#1080,#1081,#1082,#1083,#1084,#1085,#1086,
#1087,#1088));
#1090=FACE_BOUND('',#1089,.T.);
#1091=ADVANCED_FACE('F257',(#1090),#1069,.F.);
#1092=CARTESIAN_POINT('',(-149.,-46.2222222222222,0.));
#1093=DIRECTION('',(0.,1.,0.));
#1094=DIRECTION('',(0.,0.,1.));
#1095=AXIS2_PLACEMENT_3D('',#1092,#1093,#1094);
#1096=CYLINDRICAL_SURFACE('',#1095,19.9999999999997);
#1097=ORIENTED_EDGE('',*,*,#592,.T.);
#1098=ORIENTED_EDGE('',*,*,#1075,.F.);
#1099=ORIENTED_EDGE('',*,*,#807,.T.);
#1100=DIRECTION('',(0.,1.,0.));
#1101=VECTOR('',#1100,1.);
#1102=CARTESIAN_POINT('',(-149.,-46.2222222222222,-19.9999999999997));
#1103=LINE('',#1102,#1101);
#1104=EDGE_CURVE('E305',#591,#755,#1103,.T.);
#1105=ORIENTED_EDGE('',*,*,#1104,.F.);
#1106=EDGE_LOOP('',(#1097,#1098,#1099,#1105));
#1107=FACE_BOUND('',#1106,.T.);
#1108=ADVANCED_FACE('F252',(#1107),#1096,.F.);
#1109=CARTESIAN_POINT('',(-264.,-46.2222222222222,-19.9999999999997));
#1110=DIRECTION('',(0.,0.,-1.));
#1111=DIRECTION('',(-1.,0.,0.));
#1112=AXIS2_PLACEMENT_3D('',#1109,#1110,#1111);
#1113=PLANE('',#1112);
#1114=ORIENTED_EDGE('',*,*,#600,.T.);
#1115=ORIENTED_EDGE('',*,*,#1104,.T.);
#1116=ORIENTED_EDGE('',*,*,#756,.T.);
#1117=ORIENTED_EDGE('',*,*,#687,.T.);
#1118=ORIENTED_EDGE('',*,*,#645,.F.);
#1119=EDGE_LOOP('',(#1114,#1115,#1116,#1117,#1118));
#1120=FACE_BOUND('',#1119,.T.);
#1121=ADVANCED_FACE('F249',(#1120),#1113,.F.);
#1122=ORIENTED_EDGE('',*,*,#520,.T.);
#1123=EDGE_CURVE('E304',#870,#460,#1103,.T.);
#1124=ORIENTED_EDGE('',*,*,#1123,.F.);
#1125=ORIENTED_EDGE('',*,*,#871,.T.);
#1126=ORIENTED_EDGE('',*,*,#1047,.T.);
#1127=EDGE_LOOP('',(#1122,#1124,#1125,#1126));
#1128=FACE_BOUND('',#1127,.T.);
#1129=ADVANCED_FACE('F247',(#1128),#1096,.F.);
#1130=ORIENTED_EDGE('',*,*,#463,.T.);
#1131=ORIENTED_EDGE('',*,*,#640,.F.);
#1132=ORIENTED_EDGE('',*,*,#702,.T.);
#1133=ORIENTED_EDGE('',*,*,#914,.T.);
#1134=ORIENTED_EDGE('',*,*,#1123,.T.);
#1135=EDGE_LOOP('',(#1130,#1131,#1132,#1133,#1134));
#1136=FACE_BOUND('',#1135,.T.);
#1137=ADVANCED_FACE('F241',(#1136),#1113,.F.);
#1138=CARTESIAN_POINT('',(-242.,0.,-49.5555555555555));
#1139=DIRECTION('',(0.,0.,1.));
#1140=DIRECTION('',(1.,0.,0.));
#1141=AXIS2_PLACEMENT_3D('',#1138,#1139,#1140);
#1142=CYLINDRICAL_SURFACE('',#1141,12.);
#1143=CARTESIAN_POINT('',(-242.,0.,-38.));
#1144=DIRECTION('',(0.,0.,1.));
#1145=DIRECTION('',(0.,-1.,0.));
#1146=AXIS2_PLACEMENT_3D('',#1143,#1144,#1145);
#1147=CIRCLE('',#1146,12.);
#1148=CARTESIAN_POINT('',(-242.,-12.,-38.));
#1149=VERTEX_POINT('',#1148);
#1150=EDGE_CURVE('E651',#1149,#1149,#1147,.F.);
#1151=ORIENTED_EDGE('',*,*,#1150,.T.);
#1152=EDGE_LOOP('',(#1151));
#1153=FACE_BOUND('',#1152,.T.);
#1154=ORIENTED_EDGE('',*,*,#451,.T.);
#1155=EDGE_LOOP('',(#1154));
#1156=FACE_BOUND('',#1155,.T.);
#1157=ADVANCED_FACE('F246',(#1153,#1156),#1142,.F.);
#1158=CARTESIAN_POINT('',(-219.,43.6816859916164,-38.));
#1159=DIRECTION('',(0.,0.,1.));
#1160=DIRECTION('',(0.,-1.,0.));
#1161=AXIS2_PLACEMENT_3D('',#1158,#1159,#1160);
#1162=PLANE('',#1161);
#1163=ORIENTED_EDGE('',*,*,#663,.T.);
#1164=ORIENTED_EDGE('',*,*,#625,.T.);
#1165=ORIENTED_EDGE('',*,*,#678,.T.);
#1166=DIRECTION('',(0.,1.,0.));
#1167=VECTOR('',#1166,1.);
#1168=CARTESIAN_POINT('',(-219.,43.6816859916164,-38.));
#1169=LINE('',#1168,#1167);
#1170=EDGE_CURVE('E47',#662,#671,#1169,.T.);
#1171=ORIENTED_EDGE('',*,*,#1170,.F.);
#1172=EDGE_LOOP('',(#1163,#1164,#1165,#1171));
#1173=FACE_BOUND('',#1172,.T.);
#1174=ORIENTED_EDGE('',*,*,#1150,.F.);
#1175=EDGE_LOOP('',(#1174));
#1176=FACE_BOUND('',#1175,.T.);
#1177=ADVANCED_FACE('F178',(#1173,#1176),#1162,.F.);
#1178=CARTESIAN_POINT('',(-219.,-43.6816859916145,-70.8073422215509));
#1179=DIRECTION('',(-1.,0.,0.));
#1180=DIRECTION('',(0.,0.,1.));
#1181=AXIS2_PLACEMENT_3D('',#1178,#1179,#1180);
#1182=PLANE('',#1181);
#1183=ORIENTED_EDGE('',*,*,#1170,.T.);
#1184=ORIENTED_EDGE('',*,*,#672,.F.);
#1185=EDGE_LOOP('',(#1183,#1184));
#1186=FACE_BOUND('',#1185,.T.);
#1187=ADVANCED_FACE('F635',(#1186),#1182,.T.);
#1188=CLOSED_SHELL('',(#60,#92,#124,#156,#188,#220,#252,#284,#611,#651,#707,#919,#951,#983,
#1015,#1037,#1064,#1091,#1108,#1121,#1129,#1137,#1157,#1177,#1187));
#1189=MANIFOLD_SOLID_BREP('B2',#1188);
#1190=ADVANCED_BREP_SHAPE_REPRESENTATION('',(#18,#1189),#14);
#1191=SHAPE_DEFINITION_REPRESENTATION(#9,#1190);
ENDSEC;
END-ISO-10303-21;
